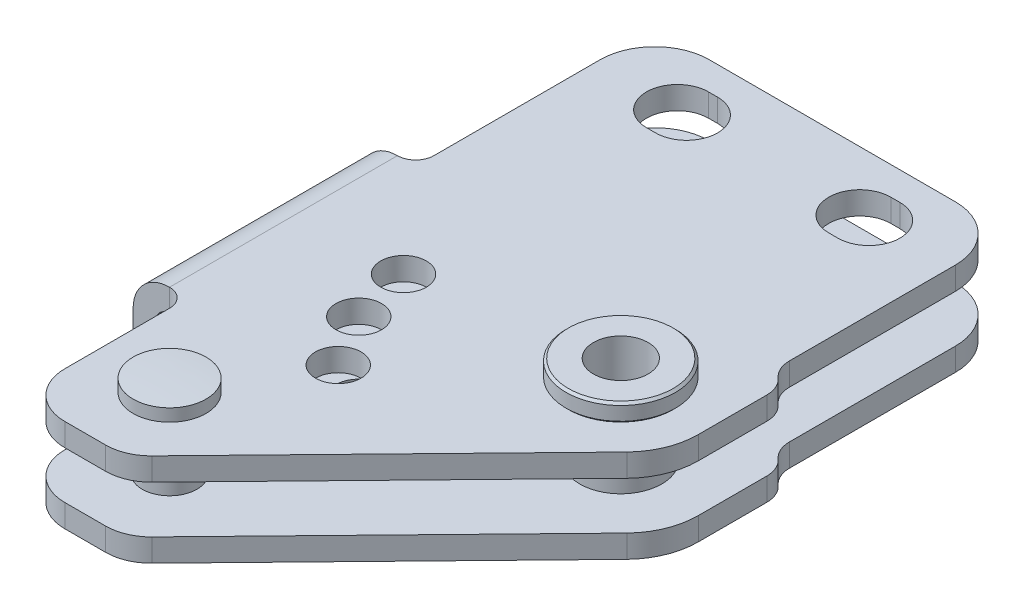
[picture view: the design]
ISO-10303-21;
HEADER;
FILE_DESCRIPTION(('STEP AP214'),'2;1');
FILE_NAME('part.step','',(''),(''),'','','');
FILE_SCHEMA(('AUTOMOTIVE_DESIGN { 1 0 10303 214 1 1 1 1 }'));
ENDSEC;
DATA;
#1=APPLICATION_CONTEXT('core data for automotive mechanical design processes');
#2=APPLICATION_PROTOCOL_DEFINITION('international standard','automotive_design',2000,#1);
#3=PRODUCT_CONTEXT('',#1,'mechanical');
#4=PRODUCT('Part','Part','',(#3));
#5=PRODUCT_RELATED_PRODUCT_CATEGORY('part','',(#4));
#6=PRODUCT_DEFINITION_FORMATION('','',#4);
#7=PRODUCT_DEFINITION_CONTEXT('part definition',#1,'design');
#8=PRODUCT_DEFINITION('design','',#6,#7);
#9=PRODUCT_DEFINITION_SHAPE('','',#8);
#10=(LENGTH_UNIT() NAMED_UNIT(*) SI_UNIT(.MILLI.,.METRE.));
#11=(NAMED_UNIT(*) PLANE_ANGLE_UNIT() SI_UNIT($,.RADIAN.));
#12=(NAMED_UNIT(*) SI_UNIT($,.STERADIAN.) SOLID_ANGLE_UNIT());
#13=UNCERTAINTY_MEASURE_WITH_UNIT(LENGTH_MEASURE(1.E-05),#10,'distance_accuracy_value','');
#14=(GEOMETRIC_REPRESENTATION_CONTEXT(3) GLOBAL_UNCERTAINTY_ASSIGNED_CONTEXT((#13)) GLOBAL_UNIT_ASSIGNED_CONTEXT((#10,
#11,#12)) REPRESENTATION_CONTEXT('',''));
#15=CARTESIAN_POINT('',(0.,0.,0.));
#16=DIRECTION('',(0.,0.,1.));
#17=DIRECTION('',(1.,0.,0.));
#18=AXIS2_PLACEMENT_3D('',#15,#16,#17);
#19=CARTESIAN_POINT('',(22.5,-5.1,28.72));
#20=DIRECTION('',(0.,-1.,0.));
#21=DIRECTION('',(-1.,0.,0.));
#22=AXIS2_PLACEMENT_3D('',#19,#20,#21);
#23=CYLINDRICAL_SURFACE('',#22,6.);
#24=CARTESIAN_POINT('',(22.5,-6.85,28.72));
#25=DIRECTION('',(0.,-1.,0.));
#26=DIRECTION('',(1.,0.,0.));
#27=AXIS2_PLACEMENT_3D('',#24,#25,#26);
#28=CIRCLE('',#27,6.);
#29=CARTESIAN_POINT('',(28.5,-6.85,28.72));
#30=VERTEX_POINT('',#29);
#31=EDGE_CURVE('E9',#30,#30,#28,.F.);
#32=ORIENTED_EDGE('',*,*,#31,.T.);
#33=EDGE_LOOP('',(#32));
#34=FACE_BOUND('',#33,.T.);
#35=CARTESIAN_POINT('',(22.5,-5.3,28.72));
#36=DIRECTION('',(0.,-1.,0.));
#37=DIRECTION('',(-1.,0.,0.));
#38=AXIS2_PLACEMENT_3D('',#35,#36,#37);
#39=CIRCLE('',#38,6.);
#40=CARTESIAN_POINT('',(16.5,-5.3,28.72));
#41=VERTEX_POINT('',#40);
#42=EDGE_CURVE('E393',#41,#41,#39,.T.);
#43=ORIENTED_EDGE('',*,*,#42,.T.);
#44=EDGE_LOOP('',(#43));
#45=FACE_BOUND('',#44,.T.);
#46=ADVANCED_FACE('F14',(#34,#45),#23,.T.);
#47=CARTESIAN_POINT('',(22.5,-7.,28.72));
#48=DIRECTION('',(0.,1.,0.));
#49=DIRECTION('',(1.,0.,0.));
#50=AXIS2_PLACEMENT_3D('',#47,#48,#49);
#51=CYLINDRICAL_SURFACE('',#50,3.);
#52=CARTESIAN_POINT('',(22.5,7.1,28.72));
#53=DIRECTION('',(0.,1.,0.));
#54=DIRECTION('',(1.,0.,0.));
#55=AXIS2_PLACEMENT_3D('',#52,#53,#54);
#56=CIRCLE('',#55,3.);
#57=CARTESIAN_POINT('',(25.5,7.1,28.72));
#58=VERTEX_POINT('',#57);
#59=EDGE_CURVE('E414',#58,#58,#56,.T.);
#60=ORIENTED_EDGE('',*,*,#59,.T.);
#61=EDGE_LOOP('',(#60));
#62=FACE_BOUND('',#61,.T.);
#63=CARTESIAN_POINT('',(22.5,-7.1,28.72));
#64=DIRECTION('',(0.,-1.,0.));
#65=DIRECTION('',(1.,0.,0.));
#66=AXIS2_PLACEMENT_3D('',#63,#64,#65);
#67=CIRCLE('',#66,3.);
#68=CARTESIAN_POINT('',(25.5,-7.1,28.72));
#69=VERTEX_POINT('',#68);
#70=EDGE_CURVE('E385',#69,#69,#67,.F.);
#71=ORIENTED_EDGE('',*,*,#70,.F.);
#72=EDGE_LOOP('',(#71));
#73=FACE_BOUND('',#72,.T.);
#74=ADVANCED_FACE('F957',(#62,#73),#51,.F.);
#75=CARTESIAN_POINT('',(22.5,-5.1,28.72));
#76=DIRECTION('',(0.,-1.,0.));
#77=DIRECTION('',(-1.,0.,0.));
#78=AXIS2_PLACEMENT_3D('',#75,#76,#77);
#79=CONICAL_SURFACE('',#78,5.8,0.785398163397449);
#80=ORIENTED_EDGE('',*,*,#42,.F.);
#81=EDGE_LOOP('',(#80));
#82=FACE_BOUND('',#81,.T.);
#83=CARTESIAN_POINT('',(22.5,-5.1,28.72));
#84=DIRECTION('',(0.,-1.,0.));
#85=DIRECTION('',(-1.,0.,0.));
#86=AXIS2_PLACEMENT_3D('',#83,#84,#85);
#87=CIRCLE('',#86,5.8);
#88=CARTESIAN_POINT('',(16.7,-5.1,28.72));
#89=VERTEX_POINT('',#88);
#90=EDGE_CURVE('E389',#89,#89,#87,.T.);
#91=ORIENTED_EDGE('',*,*,#90,.T.);
#92=EDGE_LOOP('',(#91));
#93=FACE_BOUND('',#92,.T.);
#94=ADVANCED_FACE('F924',(#82,#93),#79,.T.);
#95=CARTESIAN_POINT('',(22.5,6.85,28.72));
#96=DIRECTION('',(0.,-1.,0.));
#97=DIRECTION('',(-1.,0.,0.));
#98=AXIS2_PLACEMENT_3D('',#95,#96,#97);
#99=CONICAL_SURFACE('',#98,6.,0.785398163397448);
#100=CARTESIAN_POINT('',(22.5,7.1,28.72));
#101=DIRECTION('',(0.,1.,0.));
#102=DIRECTION('',(1.,0.,0.));
#103=AXIS2_PLACEMENT_3D('',#100,#101,#102);
#104=CIRCLE('',#103,5.75);
#105=CARTESIAN_POINT('',(28.25,7.1,28.72));
#106=VERTEX_POINT('',#105);
#107=EDGE_CURVE('E401',#106,#106,#104,.T.);
#108=ORIENTED_EDGE('',*,*,#107,.F.);
#109=EDGE_LOOP('',(#108));
#110=FACE_BOUND('',#109,.T.);
#111=CARTESIAN_POINT('',(22.5,6.85,28.72));
#112=DIRECTION('',(0.,1.,0.));
#113=DIRECTION('',(1.,0.,0.));
#114=AXIS2_PLACEMENT_3D('',#111,#112,#113);
#115=CIRCLE('',#114,6.);
#116=CARTESIAN_POINT('',(28.5,6.85,28.72));
#117=VERTEX_POINT('',#116);
#118=EDGE_CURVE('E404',#117,#117,#115,.T.);
#119=ORIENTED_EDGE('',*,*,#118,.T.);
#120=EDGE_LOOP('',(#119));
#121=FACE_BOUND('',#120,.T.);
#122=ADVANCED_FACE('F972',(#110,#121),#99,.T.);
#123=CARTESIAN_POINT('',(22.5,-7.,28.72));
#124=DIRECTION('',(0.,1.,0.));
#125=DIRECTION('',(1.,0.,0.));
#126=AXIS2_PLACEMENT_3D('',#123,#124,#125);
#127=CYLINDRICAL_SURFACE('',#126,6.);
#128=ORIENTED_EDGE('',*,*,#118,.F.);
#129=EDGE_LOOP('',(#128));
#130=FACE_BOUND('',#129,.T.);
#131=CARTESIAN_POINT('',(22.5,5.35,28.72));
#132=DIRECTION('',(0.,1.,0.));
#133=DIRECTION('',(1.,0.,0.));
#134=AXIS2_PLACEMENT_3D('',#131,#132,#133);
#135=CIRCLE('',#134,6.);
#136=CARTESIAN_POINT('',(28.5,5.35,28.72));
#137=VERTEX_POINT('',#136);
#138=EDGE_CURVE('E408',#137,#137,#135,.T.);
#139=ORIENTED_EDGE('',*,*,#138,.T.);
#140=EDGE_LOOP('',(#139));
#141=FACE_BOUND('',#140,.T.);
#142=ADVANCED_FACE('F976',(#130,#141),#127,.T.);
#143=CARTESIAN_POINT('',(-1.,-53.4000000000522,54.7199999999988));
#144=DIRECTION('',(0.,1.,0.));
#145=DIRECTION('',(0.,0.,1.));
#146=AXIS2_PLACEMENT_3D('',#143,#144,#145);
#147=SPHERICAL_SURFACE('',#146,60.0000000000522);
#148=CARTESIAN_POINT('',(-1.,6.4665181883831,54.72));
#149=DIRECTION('',(0.,1.,0.));
#150=DIRECTION('',(-1.,0.,0.));
#151=AXIS2_PLACEMENT_3D('',#148,#149,#150);
#152=CIRCLE('',#151,4.);
#153=CARTESIAN_POINT('',(-5.,6.4665181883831,54.72));
#154=VERTEX_POINT('',#153);
#155=EDGE_CURVE('E436',#154,#154,#152,.T.);
#156=ORIENTED_EDGE('',*,*,#155,.T.);
#157=EDGE_LOOP('',(#156));
#158=FACE_BOUND('',#157,.T.);
#159=ADVANCED_FACE('F955',(#158),#147,.T.);
#160=CARTESIAN_POINT('',(22.5,5.1,28.72));
#161=DIRECTION('',(0.,1.,0.));
#162=DIRECTION('',(1.,0.,0.));
#163=AXIS2_PLACEMENT_3D('',#160,#161,#162);
#164=CONICAL_SURFACE('',#163,5.75,0.785398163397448);
#165=ORIENTED_EDGE('',*,*,#138,.F.);
#166=EDGE_LOOP('',(#165));
#167=FACE_BOUND('',#166,.T.);
#168=CARTESIAN_POINT('',(22.5,5.1,28.72));
#169=DIRECTION('',(0.,1.,0.));
#170=DIRECTION('',(1.,0.,0.));
#171=AXIS2_PLACEMENT_3D('',#168,#169,#170);
#172=CIRCLE('',#171,5.75);
#173=CARTESIAN_POINT('',(28.25,5.1,28.72));
#174=VERTEX_POINT('',#173);
#175=EDGE_CURVE('E411',#174,#174,#172,.T.);
#176=ORIENTED_EDGE('',*,*,#175,.T.);
#177=EDGE_LOOP('',(#176));
#178=FACE_BOUND('',#177,.T.);
#179=ADVANCED_FACE('F981',(#167,#178),#164,.T.);
#180=CARTESIAN_POINT('',(-1.,-3.4452994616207,54.72));
#181=DIRECTION('',(0.,1.,0.));
#182=DIRECTION('',(-1.,0.,0.));
#183=AXIS2_PLACEMENT_3D('',#180,#181,#182);
#184=CYLINDRICAL_SURFACE('',#183,4.);
#185=CARTESIAN_POINT('',(-1.,5.1,54.72));
#186=DIRECTION('',(0.,1.,0.));
#187=DIRECTION('',(-1.,0.,0.));
#188=AXIS2_PLACEMENT_3D('',#185,#186,#187);
#189=CIRCLE('',#188,4.);
#190=CARTESIAN_POINT('',(-5.,5.1,54.72));
#191=VERTEX_POINT('',#190);
#192=EDGE_CURVE('E433',#191,#191,#189,.T.);
#193=ORIENTED_EDGE('',*,*,#192,.T.);
#194=EDGE_LOOP('',(#193));
#195=FACE_BOUND('',#194,.T.);
#196=ORIENTED_EDGE('',*,*,#155,.F.);
#197=EDGE_LOOP('',(#196));
#198=FACE_BOUND('',#197,.T.);
#199=ADVANCED_FACE('F984',(#195,#198),#184,.T.);
#200=CARTESIAN_POINT('',(1.,5.1,-3.4));
#201=DIRECTION('',(0.,0.,1.));
#202=DIRECTION('',(0.,1.,0.));
#203=AXIS2_PLACEMENT_3D('',#200,#201,#202);
#204=PLANE('',#203);
#205=DIRECTION('',(0.,-1.,0.));
#206=VECTOR('',#205,1.);
#207=CARTESIAN_POINT('',(1.,5.1,-3.4));
#208=LINE('',#207,#206);
#209=CARTESIAN_POINT('',(1.,5.1,-3.4));
#210=VERTEX_POINT('',#209);
#211=CARTESIAN_POINT('',(1.,2.6,-3.4));
#212=VERTEX_POINT('',#211);
#213=EDGE_CURVE('E448',#210,#212,#208,.T.);
#214=ORIENTED_EDGE('',*,*,#213,.F.);
#215=DIRECTION('',(-1.,0.,0.));
#216=VECTOR('',#215,1.);
#217=CARTESIAN_POINT('',(1.,5.1,-3.4));
#218=LINE('',#217,#216);
#219=CARTESIAN_POINT('',(0.,5.1,-3.4));
#220=VERTEX_POINT('',#219);
#221=EDGE_CURVE('E442',#210,#220,#218,.T.);
#222=ORIENTED_EDGE('',*,*,#221,.T.);
#223=DIRECTION('',(0.,-1.,0.));
#224=VECTOR('',#223,1.);
#225=CARTESIAN_POINT('',(0.,5.1,-3.4));
#226=LINE('',#225,#224);
#227=CARTESIAN_POINT('',(0.,2.6,-3.4));
#228=VERTEX_POINT('',#227);
#229=EDGE_CURVE('E360',#220,#228,#226,.T.);
#230=ORIENTED_EDGE('',*,*,#229,.T.);
#231=DIRECTION('',(-1.,0.,0.));
#232=VECTOR('',#231,1.);
#233=CARTESIAN_POINT('',(34.5,2.6,-3.4));
#234=LINE('',#233,#232);
#235=EDGE_CURVE('E376',#212,#228,#234,.T.);
#236=ORIENTED_EDGE('',*,*,#235,.F.);
#237=EDGE_LOOP('',(#214,#222,#230,#236));
#238=FACE_BOUND('',#237,.T.);
#239=ADVANCED_FACE('F1093',(#238),#204,.T.);
#240=CARTESIAN_POINT('',(1.,5.1,0.));
#241=DIRECTION('',(0.,-1.,0.));
#242=DIRECTION('',(1.,0.,0.));
#243=AXIS2_PLACEMENT_3D('',#240,#241,#242);
#244=CYLINDRICAL_SURFACE('',#243,3.4);
#245=DIRECTION('',(0.,-1.,0.));
#246=VECTOR('',#245,1.);
#247=CARTESIAN_POINT('',(1.,5.1,3.4));
#248=LINE('',#247,#246);
#249=CARTESIAN_POINT('',(1.,5.1,3.4));
#250=VERTEX_POINT('',#249);
#251=CARTESIAN_POINT('',(1.,2.6,3.4));
#252=VERTEX_POINT('',#251);
#253=EDGE_CURVE('E367',#250,#252,#248,.T.);
#254=ORIENTED_EDGE('',*,*,#253,.F.);
#255=CARTESIAN_POINT('',(1.,5.1,0.));
#256=DIRECTION('',(0.,1.,0.));
#257=DIRECTION('',(-1.,0.,0.));
#258=AXIS2_PLACEMENT_3D('',#255,#256,#257);
#259=CIRCLE('',#258,3.4);
#260=EDGE_CURVE('E440',#250,#210,#259,.T.);
#261=ORIENTED_EDGE('',*,*,#260,.T.);
#262=ORIENTED_EDGE('',*,*,#213,.T.);
#263=CARTESIAN_POINT('',(1.,2.6,0.));
#264=DIRECTION('',(0.,-1.,0.));
#265=DIRECTION('',(1.,0.,0.));
#266=AXIS2_PLACEMENT_3D('',#263,#264,#265);
#267=CIRCLE('',#266,3.4);
#268=EDGE_CURVE('E371',#252,#212,#267,.F.);
#269=ORIENTED_EDGE('',*,*,#268,.F.);
#270=EDGE_LOOP('',(#254,#261,#262,#269));
#271=FACE_BOUND('',#270,.T.);
#272=ADVANCED_FACE('F1104',(#271),#244,.F.);
#273=CARTESIAN_POINT('',(0.,5.1,3.4));
#274=DIRECTION('',(0.,0.,-1.));
#275=DIRECTION('',(0.,-1.,0.));
#276=AXIS2_PLACEMENT_3D('',#273,#274,#275);
#277=PLANE('',#276);
#278=DIRECTION('',(0.,-1.,0.));
#279=VECTOR('',#278,1.);
#280=CARTESIAN_POINT('',(0.,5.1,3.4));
#281=LINE('',#280,#279);
#282=CARTESIAN_POINT('',(0.,5.1,3.4));
#283=VERTEX_POINT('',#282);
#284=CARTESIAN_POINT('',(0.,2.6,3.4));
#285=VERTEX_POINT('',#284);
#286=EDGE_CURVE('E350',#283,#285,#281,.T.);
#287=ORIENTED_EDGE('',*,*,#286,.F.);
#288=DIRECTION('',(1.,0.,0.));
#289=VECTOR('',#288,1.);
#290=CARTESIAN_POINT('',(0.,5.1,3.4));
#291=LINE('',#290,#289);
#292=EDGE_CURVE('E387',#283,#250,#291,.T.);
#293=ORIENTED_EDGE('',*,*,#292,.T.);
#294=ORIENTED_EDGE('',*,*,#253,.T.);
#295=DIRECTION('',(1.,0.,0.));
#296=VECTOR('',#295,1.);
#297=CARTESIAN_POINT('',(34.5,2.6,3.4));
#298=LINE('',#297,#296);
#299=EDGE_CURVE('E364',#285,#252,#298,.T.);
#300=ORIENTED_EDGE('',*,*,#299,.F.);
#301=EDGE_LOOP('',(#287,#293,#294,#300));
#302=FACE_BOUND('',#301,.T.);
#303=ADVANCED_FACE('F365',(#302),#277,.T.);
#304=CARTESIAN_POINT('',(0.,5.1,0.));
#305=DIRECTION('',(0.,-1.,0.));
#306=DIRECTION('',(1.,0.,0.));
#307=AXIS2_PLACEMENT_3D('',#304,#305,#306);
#308=CYLINDRICAL_SURFACE('',#307,3.4);
#309=ORIENTED_EDGE('',*,*,#229,.F.);
#310=CARTESIAN_POINT('',(0.,5.1,0.));
#311=DIRECTION('',(0.,1.,0.));
#312=DIRECTION('',(1.,0.,0.));
#313=AXIS2_PLACEMENT_3D('',#310,#311,#312);
#314=CIRCLE('',#313,3.4);
#315=EDGE_CURVE('E357',#220,#283,#314,.T.);
#316=ORIENTED_EDGE('',*,*,#315,.T.);
#317=ORIENTED_EDGE('',*,*,#286,.T.);
#318=CARTESIAN_POINT('',(0.,2.6,0.));
#319=DIRECTION('',(0.,-1.,0.));
#320=DIRECTION('',(1.,0.,0.));
#321=AXIS2_PLACEMENT_3D('',#318,#319,#320);
#322=CIRCLE('',#321,3.4);
#323=EDGE_CURVE('E354',#228,#285,#322,.F.);
#324=ORIENTED_EDGE('',*,*,#323,.F.);
#325=EDGE_LOOP('',(#309,#316,#317,#324));
#326=FACE_BOUND('',#325,.T.);
#327=ADVANCED_FACE('F352',(#326),#308,.F.);
#328=CARTESIAN_POINT('',(5.647022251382,5.1,42.861327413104));
#329=DIRECTION('',(0.,-1.,0.));
#330=DIRECTION('',(1.,0.,0.));
#331=AXIS2_PLACEMENT_3D('',#328,#329,#330);
#332=CYLINDRICAL_SURFACE('',#331,2.5);
#333=CARTESIAN_POINT('',(5.647022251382,2.6,42.861327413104));
#334=DIRECTION('',(0.,-1.,0.));
#335=DIRECTION('',(1.,0.,0.));
#336=AXIS2_PLACEMENT_3D('',#333,#334,#335);
#337=CIRCLE('',#336,2.5);
#338=CARTESIAN_POINT('',(8.147022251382,2.6,42.861327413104));
#339=VERTEX_POINT('',#338);
#340=EDGE_CURVE('E521',#339,#339,#337,.F.);
#341=ORIENTED_EDGE('',*,*,#340,.F.);
#342=EDGE_LOOP('',(#341));
#343=FACE_BOUND('',#342,.T.);
#344=CARTESIAN_POINT('',(5.647022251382,5.1,42.861327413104));
#345=DIRECTION('',(0.,1.,0.));
#346=DIRECTION('',(-1.,0.,0.));
#347=AXIS2_PLACEMENT_3D('',#344,#345,#346);
#348=CIRCLE('',#347,2.5);
#349=CARTESIAN_POINT('',(3.147022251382,5.1,42.861327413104));
#350=VERTEX_POINT('',#349);
#351=EDGE_CURVE('E518',#350,#350,#348,.T.);
#352=ORIENTED_EDGE('',*,*,#351,.T.);
#353=EDGE_LOOP('',(#352));
#354=FACE_BOUND('',#353,.T.);
#355=ADVANCED_FACE('F1091',(#343,#354),#332,.F.);
#356=CARTESIAN_POINT('',(0.583716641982,5.1,30.637426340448));
#357=DIRECTION('',(0.,-1.,0.));
#358=DIRECTION('',(1.,0.,0.));
#359=AXIS2_PLACEMENT_3D('',#356,#357,#358);
#360=CYLINDRICAL_SURFACE('',#359,2.5);
#361=CARTESIAN_POINT('',(0.583716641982,2.6,30.637426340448));
#362=DIRECTION('',(0.,-1.,0.));
#363=DIRECTION('',(1.,0.,0.));
#364=AXIS2_PLACEMENT_3D('',#361,#362,#363);
#365=CIRCLE('',#364,2.5);
#366=CARTESIAN_POINT('',(3.083716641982,2.6,30.637426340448));
#367=VERTEX_POINT('',#366);
#368=EDGE_CURVE('E537',#367,#367,#365,.F.);
#369=ORIENTED_EDGE('',*,*,#368,.F.);
#370=EDGE_LOOP('',(#369));
#371=FACE_BOUND('',#370,.T.);
#372=CARTESIAN_POINT('',(0.583716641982,5.1,30.637426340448));
#373=DIRECTION('',(0.,1.,0.));
#374=DIRECTION('',(-1.,0.,0.));
#375=AXIS2_PLACEMENT_3D('',#372,#373,#374);
#376=CIRCLE('',#375,2.5);
#377=CARTESIAN_POINT('',(-1.916283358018,5.1,30.637426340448));
#378=VERTEX_POINT('',#377);
#379=EDGE_CURVE('E534',#378,#378,#376,.T.);
#380=ORIENTED_EDGE('',*,*,#379,.T.);
#381=EDGE_LOOP('',(#380));
#382=FACE_BOUND('',#381,.T.);
#383=ADVANCED_FACE('F1099',(#371,#382),#360,.F.);
#384=CARTESIAN_POINT('',(-2.99999999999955,-5.1,-0.49999999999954));
#385=DIRECTION('',(0.,1.,0.));
#386=DIRECTION('',(-1.,0.,0.));
#387=AXIS2_PLACEMENT_3D('',#384,#385,#386);
#388=CYLINDRICAL_SURFACE('',#387,6.00000000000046);
#389=DIRECTION('',(0.,1.,0.));
#390=VECTOR('',#389,1.);
#391=CARTESIAN_POINT('',(-3.,-5.1,-6.5));
#392=LINE('',#391,#390);
#393=CARTESIAN_POINT('',(-2.99999999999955,2.6,-6.5));
#394=VERTEX_POINT('',#393);
#395=CARTESIAN_POINT('',(-3.,5.1,-6.5));
#396=VERTEX_POINT('',#395);
#397=EDGE_CURVE('E820',#394,#396,#392,.T.);
#398=ORIENTED_EDGE('',*,*,#397,.F.);
#399=CARTESIAN_POINT('',(-2.99999999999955,2.6,-0.49999999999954));
#400=DIRECTION('',(0.,-1.,0.));
#401=DIRECTION('',(1.,0.,0.));
#402=AXIS2_PLACEMENT_3D('',#399,#400,#401);
#403=CIRCLE('',#402,6.00000000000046);
#404=CARTESIAN_POINT('',(-9.,2.6,-0.49999999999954));
#405=VERTEX_POINT('',#404);
#406=EDGE_CURVE('E624',#394,#405,#403,.F.);
#407=ORIENTED_EDGE('',*,*,#406,.T.);
#408=DIRECTION('',(0.,1.,0.));
#409=VECTOR('',#408,1.);
#410=CARTESIAN_POINT('',(-9.,-5.1,-0.49999999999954));
#411=LINE('',#410,#409);
#412=CARTESIAN_POINT('',(-9.,5.1,-0.49999999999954));
#413=VERTEX_POINT('',#412);
#414=EDGE_CURVE('E816',#405,#413,#411,.T.);
#415=ORIENTED_EDGE('',*,*,#414,.T.);
#416=CARTESIAN_POINT('',(-2.99999999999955,5.1,-0.49999999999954));
#417=DIRECTION('',(0.,1.,0.));
#418=DIRECTION('',(1.,0.,0.));
#419=AXIS2_PLACEMENT_3D('',#416,#417,#418);
#420=CIRCLE('',#419,6.00000000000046);
#421=EDGE_CURVE('E694',#396,#413,#420,.T.);
#422=ORIENTED_EDGE('',*,*,#421,.F.);
#423=EDGE_LOOP('',(#398,#407,#415,#422));
#424=FACE_BOUND('',#423,.T.);
#425=ADVANCED_FACE('F1172',(#424),#388,.T.);
#426=CARTESIAN_POINT('',(-4.00000000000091,-5.1,58.2200000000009));
#427=DIRECTION('',(0.,1.,0.));
#428=DIRECTION('',(-1.,0.,0.));
#429=AXIS2_PLACEMENT_3D('',#426,#427,#428);
#430=CYLINDRICAL_SURFACE('',#429,4.99999999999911);
#431=DIRECTION('',(0.,1.,0.));
#432=VECTOR('',#431,1.);
#433=CARTESIAN_POINT('',(-9.,-5.1,58.22));
#434=LINE('',#433,#432);
#435=CARTESIAN_POINT('',(-9.,2.6,58.22));
#436=VERTEX_POINT('',#435);
#437=CARTESIAN_POINT('',(-9.,5.1,58.22));
#438=VERTEX_POINT('',#437);
#439=EDGE_CURVE('E790',#436,#438,#434,.T.);
#440=ORIENTED_EDGE('',*,*,#439,.F.);
#441=CARTESIAN_POINT('',(-4.00000000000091,2.6,58.2200000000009));
#442=DIRECTION('',(0.,-1.,0.));
#443=DIRECTION('',(1.,0.,0.));
#444=AXIS2_PLACEMENT_3D('',#441,#442,#443);
#445=CIRCLE('',#444,4.99999999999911);
#446=CARTESIAN_POINT('',(-4.,2.6,63.22));
#447=VERTEX_POINT('',#446);
#448=EDGE_CURVE('E609',#436,#447,#445,.F.);
#449=ORIENTED_EDGE('',*,*,#448,.T.);
#450=DIRECTION('',(0.,1.,0.));
#451=VECTOR('',#450,1.);
#452=CARTESIAN_POINT('',(-4.,-5.1,63.22));
#453=LINE('',#452,#451);
#454=CARTESIAN_POINT('',(-4.,5.1,63.22));
#455=VERTEX_POINT('',#454);
#456=EDGE_CURVE('E786',#447,#455,#453,.T.);
#457=ORIENTED_EDGE('',*,*,#456,.T.);
#458=CARTESIAN_POINT('',(-4.00000000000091,5.1,58.2200000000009));
#459=DIRECTION('',(0.,1.,0.));
#460=DIRECTION('',(-1.,0.,0.));
#461=AXIS2_PLACEMENT_3D('',#458,#459,#460);
#462=CIRCLE('',#461,4.99999999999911);
#463=EDGE_CURVE('E708',#438,#455,#462,.T.);
#464=ORIENTED_EDGE('',*,*,#463,.F.);
#465=EDGE_LOOP('',(#440,#449,#457,#464));
#466=FACE_BOUND('',#465,.T.);
#467=ADVANCED_FACE('F1061',(#466),#430,.T.);
#468=CARTESIAN_POINT('',(-4.,-5.1,63.22));
#469=DIRECTION('',(0.,0.,1.));
#470=DIRECTION('',(0.,1.,0.));
#471=AXIS2_PLACEMENT_3D('',#468,#469,#470);
#472=PLANE('',#471);
#473=ORIENTED_EDGE('',*,*,#456,.F.);
#474=DIRECTION('',(-1.,0.,0.));
#475=VECTOR('',#474,1.);
#476=CARTESIAN_POINT('',(34.5,2.6,63.22));
#477=LINE('',#476,#475);
#478=CARTESIAN_POINT('',(0.480000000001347,2.6,63.22));
#479=VERTEX_POINT('',#478);
#480=EDGE_CURVE('E573',#479,#447,#477,.T.);
#481=ORIENTED_EDGE('',*,*,#480,.F.);
#482=DIRECTION('',(0.,1.,0.));
#483=VECTOR('',#482,1.);
#484=CARTESIAN_POINT('',(0.48,-5.1,63.22));
#485=LINE('',#484,#483);
#486=CARTESIAN_POINT('',(0.48,5.1,63.22));
#487=VERTEX_POINT('',#486);
#488=EDGE_CURVE('E782',#479,#487,#485,.T.);
#489=ORIENTED_EDGE('',*,*,#488,.T.);
#490=DIRECTION('',(1.,0.,0.));
#491=VECTOR('',#490,1.);
#492=CARTESIAN_POINT('',(-4.,5.1,63.22));
#493=LINE('',#492,#491);
#494=EDGE_CURVE('E710',#455,#487,#493,.T.);
#495=ORIENTED_EDGE('',*,*,#494,.F.);
#496=EDGE_LOOP('',(#473,#481,#489,#495));
#497=FACE_BOUND('',#496,.T.);
#498=ADVANCED_FACE('F1066',(#497),#472,.T.);
#499=CARTESIAN_POINT('',(0.480000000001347,-5.1,58.2200000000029));
#500=DIRECTION('',(0.,1.,0.));
#501=DIRECTION('',(-1.,0.,0.));
#502=AXIS2_PLACEMENT_3D('',#499,#500,#501);
#503=CYLINDRICAL_SURFACE('',#502,4.99999999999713);
#504=ORIENTED_EDGE('',*,*,#488,.F.);
#505=CARTESIAN_POINT('',(0.480000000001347,2.6,58.2200000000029));
#506=DIRECTION('',(0.,-1.,0.));
#507=DIRECTION('',(1.,0.,0.));
#508=AXIS2_PLACEMENT_3D('',#505,#506,#507);
#509=CIRCLE('',#508,4.99999999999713);
#510=CARTESIAN_POINT('',(4.065259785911,2.6,61.705098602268));
#511=VERTEX_POINT('',#510);
#512=EDGE_CURVE('E591',#479,#511,#509,.F.);
#513=ORIENTED_EDGE('',*,*,#512,.T.);
#514=DIRECTION('',(0.,1.,0.));
#515=VECTOR('',#514,1.);
#516=CARTESIAN_POINT('',(4.065259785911,-5.1,61.705098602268));
#517=LINE('',#516,#515);
#518=CARTESIAN_POINT('',(4.065259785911,5.1,61.705098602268));
#519=VERTEX_POINT('',#518);
#520=EDGE_CURVE('E778',#511,#519,#517,.T.);
#521=ORIENTED_EDGE('',*,*,#520,.T.);
#522=CARTESIAN_POINT('',(0.480000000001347,5.1,58.2200000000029));
#523=DIRECTION('',(0.,1.,0.));
#524=DIRECTION('',(-1.,0.,0.));
#525=AXIS2_PLACEMENT_3D('',#522,#523,#524);
#526=CIRCLE('',#525,4.99999999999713);
#527=EDGE_CURVE('E713',#487,#519,#526,.T.);
#528=ORIENTED_EDGE('',*,*,#527,.F.);
#529=EDGE_LOOP('',(#504,#513,#521,#528));
#530=FACE_BOUND('',#529,.T.);
#531=ADVANCED_FACE('F1071',(#530),#503,.T.);
#532=CARTESIAN_POINT('',(4.065259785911,-5.1,61.705098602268));
#533=DIRECTION('',(0.717051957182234,0.,0.697019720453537));
#534=DIRECTION('',(0.697019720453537,0.,-0.717051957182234));
#535=AXIS2_PLACEMENT_3D('',#532,#533,#534);
#536=PLANE('',#535);
#537=ORIENTED_EDGE('',*,*,#520,.F.);
#538=DIRECTION('',(0.697019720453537,0.,-0.717051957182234));
#539=VECTOR('',#538,1.);
#540=CARTESIAN_POINT('',(4.065259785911,2.6,61.705098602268));
#541=LINE('',#540,#539);
#542=CARTESIAN_POINT('',(29.7364156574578,2.6,35.296157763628));
#543=VERTEX_POINT('',#542);
#544=EDGE_CURVE('E588',#511,#543,#541,.T.);
#545=ORIENTED_EDGE('',*,*,#544,.T.);
#546=DIRECTION('',(0.,1.,0.));
#547=VECTOR('',#546,1.);
#548=CARTESIAN_POINT('',(29.7364156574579,-5.1,35.296157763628));
#549=LINE('',#548,#547);
#550=CARTESIAN_POINT('',(29.7364156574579,5.1,35.296157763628));
#551=VERTEX_POINT('',#550);
#552=EDGE_CURVE('E774',#543,#551,#549,.T.);
#553=ORIENTED_EDGE('',*,*,#552,.T.);
#554=DIRECTION('',(0.697019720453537,0.,-0.717051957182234));
#555=VECTOR('',#554,1.);
#556=CARTESIAN_POINT('',(4.065259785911,5.1,61.705098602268));
#557=LINE('',#556,#555);
#558=EDGE_CURVE('E716',#519,#551,#557,.T.);
#559=ORIENTED_EDGE('',*,*,#558,.F.);
#560=EDGE_LOOP('',(#537,#545,#553,#559));
#561=FACE_BOUND('',#560,.T.);
#562=ADVANCED_FACE('F1076',(#561),#536,.T.);
#563=CARTESIAN_POINT('',(24.0000000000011,-5.1,29.72));
#564=DIRECTION('',(0.,1.,0.));
#565=DIRECTION('',(-1.,0.,0.));
#566=AXIS2_PLACEMENT_3D('',#563,#564,#565);
#567=CYLINDRICAL_SURFACE('',#566,7.99999999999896);
#568=ORIENTED_EDGE('',*,*,#552,.F.);
#569=CARTESIAN_POINT('',(24.0000000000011,2.6,29.72));
#570=DIRECTION('',(0.,-1.,0.));
#571=DIRECTION('',(1.,0.,0.));
#572=AXIS2_PLACEMENT_3D('',#569,#570,#571);
#573=CIRCLE('',#572,7.99999999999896);
#574=CARTESIAN_POINT('',(32.,2.6,29.72));
#575=VERTEX_POINT('',#574);
#576=EDGE_CURVE('E844',#543,#575,#573,.F.);
#577=ORIENTED_EDGE('',*,*,#576,.T.);
#578=DIRECTION('',(0.,1.,0.));
#579=VECTOR('',#578,1.);
#580=CARTESIAN_POINT('',(32.,-5.1,29.72));
#581=LINE('',#580,#579);
#582=CARTESIAN_POINT('',(32.,5.1,29.72));
#583=VERTEX_POINT('',#582);
#584=EDGE_CURVE('E768',#575,#583,#581,.T.);
#585=ORIENTED_EDGE('',*,*,#584,.T.);
#586=CARTESIAN_POINT('',(24.0000000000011,5.1,29.72));
#587=DIRECTION('',(0.,1.,0.));
#588=DIRECTION('',(-1.,0.,0.));
#589=AXIS2_PLACEMENT_3D('',#586,#587,#588);
#590=CIRCLE('',#589,7.99999999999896);
#591=EDGE_CURVE('E719',#551,#583,#590,.T.);
#592=ORIENTED_EDGE('',*,*,#591,.F.);
#593=EDGE_LOOP('',(#568,#577,#585,#592));
#594=FACE_BOUND('',#593,.T.);
#595=ADVANCED_FACE('F944',(#594),#567,.T.);
#596=CARTESIAN_POINT('',(32.,-5.1,29.72));
#597=DIRECTION('',(1.,0.,0.));
#598=DIRECTION('',(0.,1.,0.));
#599=AXIS2_PLACEMENT_3D('',#596,#597,#598);
#600=PLANE('',#599);
#601=ORIENTED_EDGE('',*,*,#584,.F.);
#602=DIRECTION('',(0.,0.,-1.));
#603=VECTOR('',#602,1.);
#604=CARTESIAN_POINT('',(32.,2.6,29.72));
#605=LINE('',#604,#603);
#606=CARTESIAN_POINT('',(32.,2.6,22.19));
#607=VERTEX_POINT('',#606);
#608=EDGE_CURVE('E594',#575,#607,#605,.T.);
#609=ORIENTED_EDGE('',*,*,#608,.T.);
#610=DIRECTION('',(0.,1.,0.));
#611=VECTOR('',#610,1.);
#612=CARTESIAN_POINT('',(32.,-5.1,22.19));
#613=LINE('',#612,#611);
#614=CARTESIAN_POINT('',(32.,5.1,22.19));
#615=VERTEX_POINT('',#614);
#616=EDGE_CURVE('E840',#607,#615,#613,.T.);
#617=ORIENTED_EDGE('',*,*,#616,.T.);
#618=DIRECTION('',(0.,0.,-1.));
#619=VECTOR('',#618,1.);
#620=CARTESIAN_POINT('',(32.,5.1,29.72));
#621=LINE('',#620,#619);
#622=EDGE_CURVE('E678',#583,#615,#621,.T.);
#623=ORIENTED_EDGE('',*,*,#622,.F.);
#624=EDGE_LOOP('',(#601,#609,#617,#623));
#625=FACE_BOUND('',#624,.T.);
#626=ADVANCED_FACE('F1226',(#625),#600,.T.);
#627=CARTESIAN_POINT('',(29.0000000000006,-5.1,22.1899999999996));
#628=DIRECTION('',(0.,1.,0.));
#629=DIRECTION('',(-1.,0.,0.));
#630=AXIS2_PLACEMENT_3D('',#627,#628,#629);
#631=CYLINDRICAL_SURFACE('',#630,2.99999999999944);
#632=ORIENTED_EDGE('',*,*,#616,.F.);
#633=CARTESIAN_POINT('',(29.0000000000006,2.6,22.1899999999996));
#634=DIRECTION('',(0.,-1.,0.));
#635=DIRECTION('',(1.,0.,0.));
#636=AXIS2_PLACEMENT_3D('',#633,#634,#635);
#637=CIRCLE('',#636,2.99999999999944);
#638=CARTESIAN_POINT('',(31.,2.6,19.9539320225));
#639=VERTEX_POINT('',#638);
#640=EDGE_CURVE('E597',#607,#639,#637,.F.);
#641=ORIENTED_EDGE('',*,*,#640,.T.);
#642=DIRECTION('',(0.,1.,0.));
#643=VECTOR('',#642,1.);
#644=CARTESIAN_POINT('',(31.,-5.1,19.9539320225));
#645=LINE('',#644,#643);
#646=CARTESIAN_POINT('',(31.,5.1,19.9539320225));
#647=VERTEX_POINT('',#646);
#648=EDGE_CURVE('E836',#639,#647,#645,.T.);
#649=ORIENTED_EDGE('',*,*,#648,.T.);
#650=CARTESIAN_POINT('',(29.0000000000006,5.1,22.1899999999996));
#651=DIRECTION('',(0.,1.,0.));
#652=DIRECTION('',(-1.,0.,0.));
#653=AXIS2_PLACEMENT_3D('',#650,#651,#652);
#654=CIRCLE('',#653,2.99999999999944);
#655=EDGE_CURVE('E679',#615,#647,#654,.T.);
#656=ORIENTED_EDGE('',*,*,#655,.F.);
#657=EDGE_LOOP('',(#632,#641,#649,#656));
#658=FACE_BOUND('',#657,.T.);
#659=ADVANCED_FACE('F1313',(#658),#631,.T.);
#660=CARTESIAN_POINT('',(32.9999999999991,-5.1,17.7178640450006));
#661=DIRECTION('',(0.,1.,0.));
#662=DIRECTION('',(-1.,0.,0.));
#663=AXIS2_PLACEMENT_3D('',#660,#661,#662);
#664=CYLINDRICAL_SURFACE('',#663,2.99999999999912);
#665=ORIENTED_EDGE('',*,*,#648,.F.);
#666=CARTESIAN_POINT('',(32.9999999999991,2.6,17.7178640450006));
#667=DIRECTION('',(0.,-1.,0.));
#668=DIRECTION('',(1.,0.,0.));
#669=AXIS2_PLACEMENT_3D('',#666,#667,#668);
#670=CIRCLE('',#669,2.99999999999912);
#671=CARTESIAN_POINT('',(30.,2.6,17.717864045));
#672=VERTEX_POINT('',#671);
#673=EDGE_CURVE('E600',#639,#672,#670,.T.);
#674=ORIENTED_EDGE('',*,*,#673,.T.);
#675=DIRECTION('',(0.,1.,0.));
#676=VECTOR('',#675,1.);
#677=CARTESIAN_POINT('',(30.,-5.1,17.717864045));
#678=LINE('',#677,#676);
#679=CARTESIAN_POINT('',(30.,5.1,17.717864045));
#680=VERTEX_POINT('',#679);
#681=EDGE_CURVE('E832',#672,#680,#678,.T.);
#682=ORIENTED_EDGE('',*,*,#681,.T.);
#683=CARTESIAN_POINT('',(32.9999999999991,5.1,17.7178640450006));
#684=DIRECTION('',(0.,-1.,0.));
#685=DIRECTION('',(1.,0.,0.));
#686=AXIS2_PLACEMENT_3D('',#683,#684,#685);
#687=CIRCLE('',#686,2.99999999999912);
#688=EDGE_CURVE('E682',#647,#680,#687,.T.);
#689=ORIENTED_EDGE('',*,*,#688,.F.);
#690=EDGE_LOOP('',(#665,#674,#682,#689));
#691=FACE_BOUND('',#690,.T.);
#692=ADVANCED_FACE('F1234',(#691),#664,.F.);
#693=CARTESIAN_POINT('',(30.,-5.1,17.717864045));
#694=DIRECTION('',(1.,0.,0.));
#695=DIRECTION('',(0.,1.,0.));
#696=AXIS2_PLACEMENT_3D('',#693,#694,#695);
#697=PLANE('',#696);
#698=ORIENTED_EDGE('',*,*,#681,.F.);
#699=DIRECTION('',(0.,0.,-1.));
#700=VECTOR('',#699,1.);
#701=CARTESIAN_POINT('',(30.,2.6,17.717864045));
#702=LINE('',#701,#700);
#703=CARTESIAN_POINT('',(30.,2.6,-0.5));
#704=VERTEX_POINT('',#703);
#705=EDGE_CURVE('E603',#672,#704,#702,.T.);
#706=ORIENTED_EDGE('',*,*,#705,.T.);
#707=DIRECTION('',(0.,1.,0.));
#708=VECTOR('',#707,1.);
#709=CARTESIAN_POINT('',(30.,-5.1,-0.5));
#710=LINE('',#709,#708);
#711=CARTESIAN_POINT('',(30.,5.1,-0.5));
#712=VERTEX_POINT('',#711);
#713=EDGE_CURVE('E828',#704,#712,#710,.T.);
#714=ORIENTED_EDGE('',*,*,#713,.T.);
#715=DIRECTION('',(0.,0.,-1.));
#716=VECTOR('',#715,1.);
#717=CARTESIAN_POINT('',(30.,5.1,17.717864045));
#718=LINE('',#717,#716);
#719=EDGE_CURVE('E685',#680,#712,#718,.T.);
#720=ORIENTED_EDGE('',*,*,#719,.F.);
#721=EDGE_LOOP('',(#698,#706,#714,#720));
#722=FACE_BOUND('',#721,.T.);
#723=ADVANCED_FACE('F1237',(#722),#697,.T.);
#724=CARTESIAN_POINT('',(24.,-5.1,-0.5));
#725=DIRECTION('',(0.,1.,0.));
#726=DIRECTION('',(-1.,0.,0.));
#727=AXIS2_PLACEMENT_3D('',#724,#725,#726);
#728=CYLINDRICAL_SURFACE('',#727,6.);
#729=ORIENTED_EDGE('',*,*,#713,.F.);
#730=CARTESIAN_POINT('',(24.,2.6,-0.5));
#731=DIRECTION('',(0.,-1.,0.));
#732=DIRECTION('',(1.,0.,0.));
#733=AXIS2_PLACEMENT_3D('',#730,#731,#732);
#734=CIRCLE('',#733,6.);
#735=CARTESIAN_POINT('',(24.,2.6,-6.5));
#736=VERTEX_POINT('',#735);
#737=EDGE_CURVE('E606',#704,#736,#734,.F.);
#738=ORIENTED_EDGE('',*,*,#737,.T.);
#739=DIRECTION('',(0.,1.,0.));
#740=VECTOR('',#739,1.);
#741=CARTESIAN_POINT('',(24.,-5.1,-6.5));
#742=LINE('',#741,#740);
#743=CARTESIAN_POINT('',(24.,5.1,-6.5));
#744=VERTEX_POINT('',#743);
#745=EDGE_CURVE('E824',#736,#744,#742,.T.);
#746=ORIENTED_EDGE('',*,*,#745,.T.);
#747=CARTESIAN_POINT('',(24.,5.1,-0.5));
#748=DIRECTION('',(0.,1.,0.));
#749=DIRECTION('',(-1.,0.,0.));
#750=AXIS2_PLACEMENT_3D('',#747,#748,#749);
#751=CIRCLE('',#750,6.);
#752=EDGE_CURVE('E688',#712,#744,#751,.T.);
#753=ORIENTED_EDGE('',*,*,#752,.F.);
#754=EDGE_LOOP('',(#729,#738,#746,#753));
#755=FACE_BOUND('',#754,.T.);
#756=ADVANCED_FACE('F1242',(#755),#728,.T.);
#757=CARTESIAN_POINT('',(24.,-5.1,-6.5));
#758=DIRECTION('',(0.,0.,-1.));
#759=DIRECTION('',(0.,-1.,0.));
#760=AXIS2_PLACEMENT_3D('',#757,#758,#759);
#761=PLANE('',#760);
#762=ORIENTED_EDGE('',*,*,#745,.F.);
#763=DIRECTION('',(-1.,0.,0.));
#764=VECTOR('',#763,1.);
#765=CARTESIAN_POINT('',(34.5,2.6,-6.5));
#766=LINE('',#765,#764);
#767=EDGE_CURVE('E565',#736,#394,#766,.T.);
#768=ORIENTED_EDGE('',*,*,#767,.T.);
#769=ORIENTED_EDGE('',*,*,#397,.T.);
#770=DIRECTION('',(-1.,0.,0.));
#771=VECTOR('',#770,1.);
#772=CARTESIAN_POINT('',(24.,5.1,-6.5));
#773=LINE('',#772,#771);
#774=EDGE_CURVE('E691',#744,#396,#773,.T.);
#775=ORIENTED_EDGE('',*,*,#774,.F.);
#776=EDGE_LOOP('',(#762,#768,#769,#775));
#777=FACE_BOUND('',#776,.T.);
#778=ADVANCED_FACE('F1164',(#777),#761,.T.);
#779=CARTESIAN_POINT('',(2.17465028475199,5.1,37.139035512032));
#780=DIRECTION('',(0.,-1.,0.));
#781=DIRECTION('',(1.,0.,0.));
#782=AXIS2_PLACEMENT_3D('',#779,#780,#781);
#783=CYLINDRICAL_SURFACE('',#782,2.5);
#784=CARTESIAN_POINT('',(2.17465028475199,2.6,37.139035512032));
#785=DIRECTION('',(0.,-1.,0.));
#786=DIRECTION('',(1.,0.,0.));
#787=AXIS2_PLACEMENT_3D('',#784,#785,#786);
#788=CIRCLE('',#787,2.5);
#789=CARTESIAN_POINT('',(4.674650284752,2.6,37.139035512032));
#790=VERTEX_POINT('',#789);
#791=EDGE_CURVE('E529',#790,#790,#788,.F.);
#792=ORIENTED_EDGE('',*,*,#791,.F.);
#793=EDGE_LOOP('',(#792));
#794=FACE_BOUND('',#793,.T.);
#795=CARTESIAN_POINT('',(2.17465028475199,5.1,37.139035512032));
#796=DIRECTION('',(0.,1.,0.));
#797=DIRECTION('',(-1.,0.,0.));
#798=AXIS2_PLACEMENT_3D('',#795,#796,#797);
#799=CIRCLE('',#798,2.5);
#800=CARTESIAN_POINT('',(-0.325349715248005,5.1,37.139035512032));
#801=VERTEX_POINT('',#800);
#802=EDGE_CURVE('E526',#801,#801,#799,.T.);
#803=ORIENTED_EDGE('',*,*,#802,.T.);
#804=EDGE_LOOP('',(#803));
#805=FACE_BOUND('',#804,.T.);
#806=ADVANCED_FACE('F1136',(#794,#805),#783,.F.);
#807=CARTESIAN_POINT('',(21.,5.1,-3.4));
#808=DIRECTION('',(0.,0.,1.));
#809=DIRECTION('',(0.,1.,0.));
#810=AXIS2_PLACEMENT_3D('',#807,#808,#809);
#811=PLANE('',#810);
#812=DIRECTION('',(0.,-1.,0.));
#813=VECTOR('',#812,1.);
#814=CARTESIAN_POINT('',(21.,5.1,-3.4));
#815=LINE('',#814,#813);
#816=CARTESIAN_POINT('',(21.,5.1,-3.4));
#817=VERTEX_POINT('',#816);
#818=CARTESIAN_POINT('',(21.,2.6,-3.4));
#819=VERTEX_POINT('',#818);
#820=EDGE_CURVE('E489',#817,#819,#815,.T.);
#821=ORIENTED_EDGE('',*,*,#820,.F.);
#822=DIRECTION('',(-1.,0.,0.));
#823=VECTOR('',#822,1.);
#824=CARTESIAN_POINT('',(21.,5.1,-3.4));
#825=LINE('',#824,#823);
#826=CARTESIAN_POINT('',(20.,5.1,-3.4));
#827=VERTEX_POINT('',#826);
#828=EDGE_CURVE('E478',#817,#827,#825,.T.);
#829=ORIENTED_EDGE('',*,*,#828,.T.);
#830=DIRECTION('',(0.,-1.,0.));
#831=VECTOR('',#830,1.);
#832=CARTESIAN_POINT('',(20.,5.1,-3.4));
#833=LINE('',#832,#831);
#834=CARTESIAN_POINT('',(20.,2.6,-3.4));
#835=VERTEX_POINT('',#834);
#836=EDGE_CURVE('E486',#827,#835,#833,.T.);
#837=ORIENTED_EDGE('',*,*,#836,.T.);
#838=DIRECTION('',(-1.,0.,0.));
#839=VECTOR('',#838,1.);
#840=CARTESIAN_POINT('',(34.5,2.6,-3.4));
#841=LINE('',#840,#839);
#842=EDGE_CURVE('E884',#819,#835,#841,.T.);
#843=ORIENTED_EDGE('',*,*,#842,.F.);
#844=EDGE_LOOP('',(#821,#829,#837,#843));
#845=FACE_BOUND('',#844,.T.);
#846=ADVANCED_FACE('F1132',(#845),#811,.T.);
#847=CARTESIAN_POINT('',(21.,5.1,0.));
#848=DIRECTION('',(0.,-1.,0.));
#849=DIRECTION('',(1.,0.,0.));
#850=AXIS2_PLACEMENT_3D('',#847,#848,#849);
#851=CYLINDRICAL_SURFACE('',#850,3.4);
#852=DIRECTION('',(0.,-1.,0.));
#853=VECTOR('',#852,1.);
#854=CARTESIAN_POINT('',(21.,5.1,3.4));
#855=LINE('',#854,#853);
#856=CARTESIAN_POINT('',(21.,5.1,3.4));
#857=VERTEX_POINT('',#856);
#858=CARTESIAN_POINT('',(21.,2.6,3.4));
#859=VERTEX_POINT('',#858);
#860=EDGE_CURVE('E492',#857,#859,#855,.T.);
#861=ORIENTED_EDGE('',*,*,#860,.F.);
#862=CARTESIAN_POINT('',(21.,5.1,0.));
#863=DIRECTION('',(0.,1.,0.));
#864=DIRECTION('',(-1.,0.,0.));
#865=AXIS2_PLACEMENT_3D('',#862,#863,#864);
#866=CIRCLE('',#865,3.4);
#867=EDGE_CURVE('E476',#857,#817,#866,.T.);
#868=ORIENTED_EDGE('',*,*,#867,.T.);
#869=ORIENTED_EDGE('',*,*,#820,.T.);
#870=CARTESIAN_POINT('',(21.,2.6,0.));
#871=DIRECTION('',(0.,-1.,0.));
#872=DIRECTION('',(1.,0.,0.));
#873=AXIS2_PLACEMENT_3D('',#870,#871,#872);
#874=CIRCLE('',#873,3.4);
#875=EDGE_CURVE('E887',#859,#819,#874,.F.);
#876=ORIENTED_EDGE('',*,*,#875,.F.);
#877=EDGE_LOOP('',(#861,#868,#869,#876));
#878=FACE_BOUND('',#877,.T.);
#879=ADVANCED_FACE('F1135',(#878),#851,.F.);
#880=CARTESIAN_POINT('',(20.,5.1,3.4));
#881=DIRECTION('',(0.,0.,-1.));
#882=DIRECTION('',(0.,-1.,0.));
#883=AXIS2_PLACEMENT_3D('',#880,#881,#882);
#884=PLANE('',#883);
#885=DIRECTION('',(0.,-1.,0.));
#886=VECTOR('',#885,1.);
#887=CARTESIAN_POINT('',(20.,5.1,3.4));
#888=LINE('',#887,#886);
#889=CARTESIAN_POINT('',(20.,5.1,3.4));
#890=VERTEX_POINT('',#889);
#891=CARTESIAN_POINT('',(20.,2.6,3.4));
#892=VERTEX_POINT('',#891);
#893=EDGE_CURVE('E483',#890,#892,#888,.T.);
#894=ORIENTED_EDGE('',*,*,#893,.F.);
#895=DIRECTION('',(1.,0.,0.));
#896=VECTOR('',#895,1.);
#897=CARTESIAN_POINT('',(20.,5.1,3.4));
#898=LINE('',#897,#896);
#899=EDGE_CURVE('E475',#890,#857,#898,.T.);
#900=ORIENTED_EDGE('',*,*,#899,.T.);
#901=ORIENTED_EDGE('',*,*,#860,.T.);
#902=DIRECTION('',(1.,0.,0.));
#903=VECTOR('',#902,1.);
#904=CARTESIAN_POINT('',(34.5,2.6,3.4));
#905=LINE('',#904,#903);
#906=EDGE_CURVE('E890',#892,#859,#905,.T.);
#907=ORIENTED_EDGE('',*,*,#906,.F.);
#908=EDGE_LOOP('',(#894,#900,#901,#907));
#909=FACE_BOUND('',#908,.T.);
#910=ADVANCED_FACE('F1130',(#909),#884,.T.);
#911=CARTESIAN_POINT('',(20.,5.1,0.));
#912=DIRECTION('',(0.,-1.,0.));
#913=DIRECTION('',(1.,0.,0.));
#914=AXIS2_PLACEMENT_3D('',#911,#912,#913);
#915=CYLINDRICAL_SURFACE('',#914,3.4);
#916=ORIENTED_EDGE('',*,*,#836,.F.);
#917=CARTESIAN_POINT('',(20.,5.1,0.));
#918=DIRECTION('',(0.,1.,0.));
#919=DIRECTION('',(1.,0.,0.));
#920=AXIS2_PLACEMENT_3D('',#917,#918,#919);
#921=CIRCLE('',#920,3.4);
#922=EDGE_CURVE('E481',#827,#890,#921,.T.);
#923=ORIENTED_EDGE('',*,*,#922,.T.);
#924=ORIENTED_EDGE('',*,*,#893,.T.);
#925=CARTESIAN_POINT('',(20.,2.6,0.));
#926=DIRECTION('',(0.,-1.,0.));
#927=DIRECTION('',(1.,0.,0.));
#928=AXIS2_PLACEMENT_3D('',#925,#926,#927);
#929=CIRCLE('',#928,3.4);
#930=EDGE_CURVE('E881',#835,#892,#929,.F.);
#931=ORIENTED_EDGE('',*,*,#930,.F.);
#932=EDGE_LOOP('',(#916,#923,#924,#931));
#933=FACE_BOUND('',#932,.T.);
#934=ADVANCED_FACE('F997',(#933),#915,.F.);
#935=CARTESIAN_POINT('',(-1.,-4.6,54.72));
#936=DIRECTION('',(0.,-1.,0.));
#937=DIRECTION('',(1.,0.,0.));
#938=AXIS2_PLACEMENT_3D('',#935,#936,#937);
#939=CONICAL_SURFACE('',#938,2.,1.04719755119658);
#940=CARTESIAN_POINT('',(-1.,-3.4452994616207,54.72));
#941=VERTEX_POINT('',#940);
#942=VERTEX_LOOP('',#941);
#943=FACE_BOUND('',#942,.T.);
#944=CARTESIAN_POINT('',(-1.,-4.6,54.72));
#945=DIRECTION('',(0.,1.,0.));
#946=DIRECTION('',(-1.,0.,0.));
#947=AXIS2_PLACEMENT_3D('',#944,#945,#946);
#948=CIRCLE('',#947,2.);
#949=CARTESIAN_POINT('',(-3.,-4.6,54.72));
#950=VERTEX_POINT('',#949);
#951=EDGE_CURVE('E370',#950,#950,#948,.T.);
#952=ORIENTED_EDGE('',*,*,#951,.F.);
#953=EDGE_LOOP('',(#952));
#954=FACE_BOUND('',#953,.T.);
#955=ADVANCED_FACE('F993',(#943,#954),#939,.F.);
#956=CARTESIAN_POINT('',(-9.,-5.1,-0.5));
#957=DIRECTION('',(-1.,0.,0.));
#958=DIRECTION('',(0.,-1.,0.));
#959=AXIS2_PLACEMENT_3D('',#956,#957,#958);
#960=PLANE('',#959);
#961=ORIENTED_EDGE('',*,*,#414,.F.);
#962=DIRECTION('',(0.,0.,1.));
#963=VECTOR('',#962,1.);
#964=CARTESIAN_POINT('',(-9.,2.6,-0.5));
#965=LINE('',#964,#963);
#966=CARTESIAN_POINT('',(-9.,2.6,17.7199999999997));
#967=VERTEX_POINT('',#966);
#968=EDGE_CURVE('E621',#405,#967,#965,.T.);
#969=ORIENTED_EDGE('',*,*,#968,.T.);
#970=DIRECTION('',(0.,1.,0.));
#971=VECTOR('',#970,1.);
#972=CARTESIAN_POINT('',(-9.,-5.1,17.72));
#973=LINE('',#972,#971);
#974=CARTESIAN_POINT('',(-9.,5.1,17.72));
#975=VERTEX_POINT('',#974);
#976=EDGE_CURVE('E812',#967,#975,#973,.T.);
#977=ORIENTED_EDGE('',*,*,#976,.T.);
#978=DIRECTION('',(0.,0.,1.));
#979=VECTOR('',#978,1.);
#980=CARTESIAN_POINT('',(-9.,5.1,-0.5));
#981=LINE('',#980,#979);
#982=EDGE_CURVE('E696',#413,#975,#981,.T.);
#983=ORIENTED_EDGE('',*,*,#982,.F.);
#984=EDGE_LOOP('',(#961,#969,#977,#983));
#985=FACE_BOUND('',#984,.T.);
#986=ADVANCED_FACE('F996',(#985),#960,.T.);
#987=CARTESIAN_POINT('',(29.0000000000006,5.1,22.1899999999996));
#988=DIRECTION('',(0.,1.,0.));
#989=DIRECTION('',(-1.,0.,0.));
#990=AXIS2_PLACEMENT_3D('',#987,#988,#989);
#991=PLANE('',#990);
#992=ORIENTED_EDGE('',*,*,#192,.F.);
#993=EDGE_LOOP('',(#992));
#994=FACE_BOUND('',#993,.T.);
#995=ORIENTED_EDGE('',*,*,#867,.F.);
#996=ORIENTED_EDGE('',*,*,#899,.F.);
#997=ORIENTED_EDGE('',*,*,#922,.F.);
#998=ORIENTED_EDGE('',*,*,#828,.F.);
#999=EDGE_LOOP('',(#995,#996,#997,#998));
#1000=FACE_BOUND('',#999,.T.);
#1001=ORIENTED_EDGE('',*,*,#802,.F.);
#1002=EDGE_LOOP('',(#1001));
#1003=FACE_BOUND('',#1002,.T.);
#1004=DIRECTION('',(0.,0.,-1.));
#1005=VECTOR('',#1004,1.);
#1006=CARTESIAN_POINT('',(-11.,5.1,63.22));
#1007=LINE('',#1006,#1005);
#1008=CARTESIAN_POINT('',(-11.,5.1,44.72));
#1009=VERTEX_POINT('',#1008);
#1010=CARTESIAN_POINT('',(-11.,5.1,19.72));
#1011=VERTEX_POINT('',#1010);
#1012=EDGE_CURVE('E542',#1009,#1011,#1007,.T.);
#1013=ORIENTED_EDGE('',*,*,#1012,.F.);
#1014=CARTESIAN_POINT('',(-11.,5.1,46.72));
#1015=DIRECTION('',(0.,-1.,0.));
#1016=DIRECTION('',(-1.,0.,0.));
#1017=AXIS2_PLACEMENT_3D('',#1014,#1015,#1016);
#1018=CIRCLE('',#1017,2.00000000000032);
#1019=CARTESIAN_POINT('',(-9.,5.1,46.72));
#1020=VERTEX_POINT('',#1019);
#1021=EDGE_CURVE('E702',#1009,#1020,#1018,.T.);
#1022=ORIENTED_EDGE('',*,*,#1021,.T.);
#1023=DIRECTION('',(0.,0.,1.));
#1024=VECTOR('',#1023,1.);
#1025=CARTESIAN_POINT('',(-9.,5.1,46.72));
#1026=LINE('',#1025,#1024);
#1027=EDGE_CURVE('E705',#1020,#438,#1026,.T.);
#1028=ORIENTED_EDGE('',*,*,#1027,.T.);
#1029=ORIENTED_EDGE('',*,*,#463,.T.);
#1030=ORIENTED_EDGE('',*,*,#494,.T.);
#1031=ORIENTED_EDGE('',*,*,#527,.T.);
#1032=ORIENTED_EDGE('',*,*,#558,.T.);
#1033=ORIENTED_EDGE('',*,*,#591,.T.);
#1034=ORIENTED_EDGE('',*,*,#622,.T.);
#1035=ORIENTED_EDGE('',*,*,#655,.T.);
#1036=ORIENTED_EDGE('',*,*,#688,.T.);
#1037=ORIENTED_EDGE('',*,*,#719,.T.);
#1038=ORIENTED_EDGE('',*,*,#752,.T.);
#1039=ORIENTED_EDGE('',*,*,#774,.T.);
#1040=ORIENTED_EDGE('',*,*,#421,.T.);
#1041=ORIENTED_EDGE('',*,*,#982,.T.);
#1042=CARTESIAN_POINT('',(-11.,5.1,17.7199999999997));
#1043=DIRECTION('',(0.,-1.,0.));
#1044=DIRECTION('',(-1.,0.,0.));
#1045=AXIS2_PLACEMENT_3D('',#1042,#1043,#1044);
#1046=CIRCLE('',#1045,2.00000000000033);
#1047=EDGE_CURVE('E699',#975,#1011,#1046,.T.);
#1048=ORIENTED_EDGE('',*,*,#1047,.T.);
#1049=EDGE_LOOP('',(#1013,#1022,#1028,#1029,#1030,#1031,#1032,#1033,#1034,#1035,#1036,#1037,
#1038,#1039,#1040,#1041,#1048));
#1050=FACE_BOUND('',#1049,.T.);
#1051=ORIENTED_EDGE('',*,*,#379,.F.);
#1052=EDGE_LOOP('',(#1051));
#1053=FACE_BOUND('',#1052,.T.);
#1054=ORIENTED_EDGE('',*,*,#351,.F.);
#1055=EDGE_LOOP('',(#1054));
#1056=FACE_BOUND('',#1055,.T.);
#1057=ORIENTED_EDGE('',*,*,#260,.F.);
#1058=ORIENTED_EDGE('',*,*,#292,.F.);
#1059=ORIENTED_EDGE('',*,*,#315,.F.);
#1060=ORIENTED_EDGE('',*,*,#221,.F.);
#1061=EDGE_LOOP('',(#1057,#1058,#1059,#1060));
#1062=FACE_BOUND('',#1061,.T.);
#1063=ORIENTED_EDGE('',*,*,#175,.F.);
#1064=EDGE_LOOP('',(#1063));
#1065=FACE_BOUND('',#1064,.T.);
#1066=ADVANCED_FACE('F988',(#994,#1000,#1003,#1050,#1053,#1056,#1062,#1065),#991,.T.);
#1067=CARTESIAN_POINT('',(-9.,-5.1,46.72));
#1068=DIRECTION('',(-1.,0.,0.));
#1069=DIRECTION('',(0.,-1.,0.));
#1070=AXIS2_PLACEMENT_3D('',#1067,#1068,#1069);
#1071=PLANE('',#1070);
#1072=DIRECTION('',(0.,1.,0.));
#1073=VECTOR('',#1072,1.);
#1074=CARTESIAN_POINT('',(-9.,-5.1,46.72));
#1075=LINE('',#1074,#1073);
#1076=CARTESIAN_POINT('',(-9.,2.6,46.72));
#1077=VERTEX_POINT('',#1076);
#1078=EDGE_CURVE('E794',#1077,#1020,#1075,.T.);
#1079=ORIENTED_EDGE('',*,*,#1078,.F.);
#1080=DIRECTION('',(0.,0.,1.));
#1081=VECTOR('',#1080,1.);
#1082=CARTESIAN_POINT('',(-9.,2.6,46.72));
#1083=LINE('',#1082,#1081);
#1084=EDGE_CURVE('E612',#1077,#436,#1083,.T.);
#1085=ORIENTED_EDGE('',*,*,#1084,.T.);
#1086=ORIENTED_EDGE('',*,*,#439,.T.);
#1087=ORIENTED_EDGE('',*,*,#1027,.F.);
#1088=EDGE_LOOP('',(#1079,#1085,#1086,#1087));
#1089=FACE_BOUND('',#1088,.T.);
#1090=ADVANCED_FACE('F1011',(#1089),#1071,.T.);
#1091=CARTESIAN_POINT('',(34.5,2.6,63.22));
#1092=DIRECTION('',(0.,-1.,0.));
#1093=DIRECTION('',(1.,0.,0.));
#1094=AXIS2_PLACEMENT_3D('',#1091,#1092,#1093);
#1095=PLANE('',#1094);
#1096=ORIENTED_EDGE('',*,*,#930,.T.);
#1097=ORIENTED_EDGE('',*,*,#906,.T.);
#1098=ORIENTED_EDGE('',*,*,#875,.T.);
#1099=ORIENTED_EDGE('',*,*,#842,.T.);
#1100=EDGE_LOOP('',(#1096,#1097,#1098,#1099));
#1101=FACE_BOUND('',#1100,.T.);
#1102=ORIENTED_EDGE('',*,*,#791,.T.);
#1103=EDGE_LOOP('',(#1102));
#1104=FACE_BOUND('',#1103,.T.);
#1105=ORIENTED_EDGE('',*,*,#767,.F.);
#1106=ORIENTED_EDGE('',*,*,#737,.F.);
#1107=ORIENTED_EDGE('',*,*,#705,.F.);
#1108=ORIENTED_EDGE('',*,*,#673,.F.);
#1109=ORIENTED_EDGE('',*,*,#640,.F.);
#1110=ORIENTED_EDGE('',*,*,#608,.F.);
#1111=ORIENTED_EDGE('',*,*,#576,.F.);
#1112=ORIENTED_EDGE('',*,*,#544,.F.);
#1113=ORIENTED_EDGE('',*,*,#512,.F.);
#1114=ORIENTED_EDGE('',*,*,#480,.T.);
#1115=ORIENTED_EDGE('',*,*,#448,.F.);
#1116=ORIENTED_EDGE('',*,*,#1084,.F.);
#1117=CARTESIAN_POINT('',(-11.,2.6,46.72));
#1118=DIRECTION('',(0.,-1.,0.));
#1119=DIRECTION('',(1.,0.,0.));
#1120=AXIS2_PLACEMENT_3D('',#1117,#1118,#1119);
#1121=CIRCLE('',#1120,2.00000000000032);
#1122=CARTESIAN_POINT('',(-11.,2.6,44.72));
#1123=VERTEX_POINT('',#1122);
#1124=EDGE_CURVE('E615',#1123,#1077,#1121,.T.);
#1125=ORIENTED_EDGE('',*,*,#1124,.F.);
#1126=DIRECTION('',(0.,0.,-1.));
#1127=VECTOR('',#1126,1.);
#1128=CARTESIAN_POINT('',(-11.,2.6,63.22));
#1129=LINE('',#1128,#1127);
#1130=CARTESIAN_POINT('',(-11.,2.6,19.72));
#1131=VERTEX_POINT('',#1130);
#1132=EDGE_CURVE('E585',#1123,#1131,#1129,.T.);
#1133=ORIENTED_EDGE('',*,*,#1132,.T.);
#1134=CARTESIAN_POINT('',(-11.,2.6,17.7199999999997));
#1135=DIRECTION('',(0.,-1.,0.));
#1136=DIRECTION('',(1.,0.,0.));
#1137=AXIS2_PLACEMENT_3D('',#1134,#1135,#1136);
#1138=CIRCLE('',#1137,2.00000000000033);
#1139=EDGE_CURVE('E618',#967,#1131,#1138,.T.);
#1140=ORIENTED_EDGE('',*,*,#1139,.F.);
#1141=ORIENTED_EDGE('',*,*,#968,.F.);
#1142=ORIENTED_EDGE('',*,*,#406,.F.);
#1143=EDGE_LOOP('',(#1105,#1106,#1107,#1108,#1109,#1110,#1111,#1112,#1113,#1114,#1115,#1116,
#1125,#1133,#1140,#1141,#1142));
#1144=FACE_BOUND('',#1143,.T.);
#1145=CARTESIAN_POINT('',(-1.,2.6,54.72));
#1146=DIRECTION('',(0.,-1.,0.));
#1147=DIRECTION('',(1.,0.,0.));
#1148=AXIS2_PLACEMENT_3D('',#1145,#1146,#1147);
#1149=CIRCLE('',#1148,3.);
#1150=CARTESIAN_POINT('',(2.,2.6,54.72));
#1151=VERTEX_POINT('',#1150);
#1152=EDGE_CURVE('E439',#1151,#1151,#1149,.F.);
#1153=ORIENTED_EDGE('',*,*,#1152,.T.);
#1154=EDGE_LOOP('',(#1153));
#1155=FACE_BOUND('',#1154,.T.);
#1156=ORIENTED_EDGE('',*,*,#368,.T.);
#1157=EDGE_LOOP('',(#1156));
#1158=FACE_BOUND('',#1157,.T.);
#1159=ORIENTED_EDGE('',*,*,#340,.T.);
#1160=EDGE_LOOP('',(#1159));
#1161=FACE_BOUND('',#1160,.T.);
#1162=ORIENTED_EDGE('',*,*,#323,.T.);
#1163=ORIENTED_EDGE('',*,*,#299,.T.);
#1164=ORIENTED_EDGE('',*,*,#268,.T.);
#1165=ORIENTED_EDGE('',*,*,#235,.T.);
#1166=EDGE_LOOP('',(#1162,#1163,#1164,#1165));
#1167=FACE_BOUND('',#1166,.T.);
#1168=CARTESIAN_POINT('',(22.5,2.6,28.72));
#1169=DIRECTION('',(0.,-1.,0.));
#1170=DIRECTION('',(1.,0.,0.));
#1171=AXIS2_PLACEMENT_3D('',#1168,#1169,#1170);
#1172=CIRCLE('',#1171,4.5);
#1173=CARTESIAN_POINT('',(27.,2.6,28.72));
#1174=VERTEX_POINT('',#1173);
#1175=EDGE_CURVE('E417',#1174,#1174,#1172,.T.);
#1176=ORIENTED_EDGE('',*,*,#1175,.F.);
#1177=EDGE_LOOP('',(#1176));
#1178=FACE_BOUND('',#1177,.T.);
#1179=ADVANCED_FACE('F374',(#1101,#1104,#1144,#1155,#1158,#1161,#1167,#1178),#1095,.T.);
#1180=CARTESIAN_POINT('',(-1.,-3.4452994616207,54.72));
#1181=DIRECTION('',(0.,1.,0.));
#1182=DIRECTION('',(-1.,0.,0.));
#1183=AXIS2_PLACEMENT_3D('',#1180,#1181,#1182);
#1184=CYLINDRICAL_SURFACE('',#1183,2.);
#1185=ORIENTED_EDGE('',*,*,#951,.T.);
#1186=EDGE_LOOP('',(#1185));
#1187=FACE_BOUND('',#1186,.T.);
#1188=CARTESIAN_POINT('',(-1.,-6.5666574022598,54.72));
#1189=DIRECTION('',(0.,1.,0.));
#1190=DIRECTION('',(-1.,0.,0.));
#1191=AXIS2_PLACEMENT_3D('',#1188,#1189,#1190);
#1192=CIRCLE('',#1191,2.);
#1193=CARTESIAN_POINT('',(-0.999999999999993,-6.5666574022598,56.7200000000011));
#1194=VERTEX_POINT('',#1193);
#1195=EDGE_CURVE('E424',#1194,#1194,#1192,.T.);
#1196=ORIENTED_EDGE('',*,*,#1195,.F.);
#1197=EDGE_LOOP('',(#1196));
#1198=FACE_BOUND('',#1197,.T.);
#1199=ADVANCED_FACE('F951',(#1187,#1198),#1184,.F.);
#1200=CARTESIAN_POINT('',(-11.,-5.1,17.7199999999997));
#1201=DIRECTION('',(0.,1.,0.));
#1202=DIRECTION('',(-1.,0.,0.));
#1203=AXIS2_PLACEMENT_3D('',#1200,#1201,#1202);
#1204=CYLINDRICAL_SURFACE('',#1203,2.00000000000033);
#1205=ORIENTED_EDGE('',*,*,#976,.F.);
#1206=ORIENTED_EDGE('',*,*,#1139,.T.);
#1207=DIRECTION('',(0.,1.,0.));
#1208=VECTOR('',#1207,1.);
#1209=CARTESIAN_POINT('',(-11.,-5.1,19.72));
#1210=LINE('',#1209,#1208);
#1211=EDGE_CURVE('E808',#1131,#1011,#1210,.T.);
#1212=ORIENTED_EDGE('',*,*,#1211,.T.);
#1213=ORIENTED_EDGE('',*,*,#1047,.F.);
#1214=EDGE_LOOP('',(#1205,#1206,#1212,#1213));
#1215=FACE_BOUND('',#1214,.T.);
#1216=ADVANCED_FACE('F999',(#1215),#1204,.F.);
#1217=CARTESIAN_POINT('',(-11.,1.0999999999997,63.22));
#1218=DIRECTION('',(0.,0.,-1.));
#1219=DIRECTION('',(0.,-1.,0.));
#1220=AXIS2_PLACEMENT_3D('',#1217,#1218,#1219);
#1221=CYLINDRICAL_SURFACE('',#1220,4.0000000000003);
#1222=DIRECTION('',(0.,0.,-1.));
#1223=VECTOR('',#1222,1.);
#1224=CARTESIAN_POINT('',(-15.,1.1,63.22));
#1225=LINE('',#1224,#1223);
#1226=CARTESIAN_POINT('',(-15.,1.1,44.72));
#1227=VERTEX_POINT('',#1226);
#1228=CARTESIAN_POINT('',(-15.,1.1,19.72));
#1229=VERTEX_POINT('',#1228);
#1230=EDGE_CURVE('E544',#1227,#1229,#1225,.T.);
#1231=ORIENTED_EDGE('',*,*,#1230,.F.);
#1232=CARTESIAN_POINT('',(-11.,1.0999999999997,44.72));
#1233=DIRECTION('',(0.,0.,1.));
#1234=DIRECTION('',(0.,1.,0.));
#1235=AXIS2_PLACEMENT_3D('',#1232,#1233,#1234);
#1236=CIRCLE('',#1235,4.0000000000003);
#1237=EDGE_CURVE('E552',#1009,#1227,#1236,.T.);
#1238=ORIENTED_EDGE('',*,*,#1237,.F.);
#1239=ORIENTED_EDGE('',*,*,#1012,.T.);
#1240=CARTESIAN_POINT('',(-11.,1.0999999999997,19.72));
#1241=DIRECTION('',(0.,0.,-1.));
#1242=DIRECTION('',(0.,-1.,0.));
#1243=AXIS2_PLACEMENT_3D('',#1240,#1241,#1242);
#1244=CIRCLE('',#1243,4.0000000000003);
#1245=EDGE_CURVE('E555',#1229,#1011,#1244,.T.);
#1246=ORIENTED_EDGE('',*,*,#1245,.F.);
#1247=EDGE_LOOP('',(#1231,#1238,#1239,#1246));
#1248=FACE_BOUND('',#1247,.T.);
#1249=ADVANCED_FACE('F1006',(#1248),#1221,.T.);
#1250=CARTESIAN_POINT('',(-11.,-5.1,46.72));
#1251=DIRECTION('',(0.,1.,0.));
#1252=DIRECTION('',(-1.,0.,0.));
#1253=AXIS2_PLACEMENT_3D('',#1250,#1251,#1252);
#1254=CYLINDRICAL_SURFACE('',#1253,2.00000000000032);
#1255=DIRECTION('',(0.,1.,0.));
#1256=VECTOR('',#1255,1.);
#1257=CARTESIAN_POINT('',(-11.,-5.1,44.72));
#1258=LINE('',#1257,#1256);
#1259=EDGE_CURVE('E798',#1123,#1009,#1258,.T.);
#1260=ORIENTED_EDGE('',*,*,#1259,.F.);
#1261=ORIENTED_EDGE('',*,*,#1124,.T.);
#1262=ORIENTED_EDGE('',*,*,#1078,.T.);
#1263=ORIENTED_EDGE('',*,*,#1021,.F.);
#1264=EDGE_LOOP('',(#1260,#1261,#1262,#1263));
#1265=FACE_BOUND('',#1264,.T.);
#1266=ADVANCED_FACE('F1053',(#1265),#1254,.F.);
#1267=CARTESIAN_POINT('',(-11.,1.10000000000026,63.22));
#1268=DIRECTION('',(0.,0.,-1.));
#1269=DIRECTION('',(0.,-1.,0.));
#1270=AXIS2_PLACEMENT_3D('',#1267,#1268,#1269);
#1271=CYLINDRICAL_SURFACE('',#1270,1.49999999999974);
#1272=ORIENTED_EDGE('',*,*,#1132,.F.);
#1273=CARTESIAN_POINT('',(-11.,1.10000000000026,44.72));
#1274=DIRECTION('',(0.,0.,1.));
#1275=DIRECTION('',(0.,1.,0.));
#1276=AXIS2_PLACEMENT_3D('',#1273,#1274,#1275);
#1277=CIRCLE('',#1276,1.49999999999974);
#1278=CARTESIAN_POINT('',(-12.5,1.1,44.72));
#1279=VERTEX_POINT('',#1278);
#1280=EDGE_CURVE('E853',#1279,#1123,#1277,.F.);
#1281=ORIENTED_EDGE('',*,*,#1280,.F.);
#1282=DIRECTION('',(0.,0.,-1.));
#1283=VECTOR('',#1282,1.);
#1284=CARTESIAN_POINT('',(-12.5,1.1,63.22));
#1285=LINE('',#1284,#1283);
#1286=CARTESIAN_POINT('',(-12.5,1.1,19.72));
#1287=VERTEX_POINT('',#1286);
#1288=EDGE_CURVE('E582',#1279,#1287,#1285,.T.);
#1289=ORIENTED_EDGE('',*,*,#1288,.T.);
#1290=CARTESIAN_POINT('',(-11.,1.10000000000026,19.72));
#1291=DIRECTION('',(0.,0.,-1.));
#1292=DIRECTION('',(0.,-1.,0.));
#1293=AXIS2_PLACEMENT_3D('',#1290,#1291,#1292);
#1294=CIRCLE('',#1293,1.49999999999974);
#1295=EDGE_CURVE('E675',#1131,#1287,#1294,.F.);
#1296=ORIENTED_EDGE('',*,*,#1295,.F.);
#1297=EDGE_LOOP('',(#1272,#1281,#1289,#1296));
#1298=FACE_BOUND('',#1297,.T.);
#1299=ADVANCED_FACE('F943',(#1298),#1271,.F.);
#1300=CARTESIAN_POINT('',(-12.5,1.1,63.22));
#1301=DIRECTION('',(1.,0.,0.));
#1302=DIRECTION('',(0.,1.,0.));
#1303=AXIS2_PLACEMENT_3D('',#1300,#1301,#1302);
#1304=PLANE('',#1303);
#1305=ORIENTED_EDGE('',*,*,#1288,.F.);
#1306=DIRECTION('',(0.,1.,0.));
#1307=VECTOR('',#1306,1.);
#1308=CARTESIAN_POINT('',(-12.5,-5.1,44.72));
#1309=LINE('',#1308,#1307);
#1310=CARTESIAN_POINT('',(-12.5,-1.1,44.72));
#1311=VERTEX_POINT('',#1310);
#1312=EDGE_CURVE('E850',#1311,#1279,#1309,.T.);
#1313=ORIENTED_EDGE('',*,*,#1312,.F.);
#1314=DIRECTION('',(0.,0.,-1.));
#1315=VECTOR('',#1314,1.);
#1316=CARTESIAN_POINT('',(-12.5,-1.1,63.22));
#1317=LINE('',#1316,#1315);
#1318=CARTESIAN_POINT('',(-12.5,-1.1,19.72));
#1319=VERTEX_POINT('',#1318);
#1320=EDGE_CURVE('E579',#1311,#1319,#1317,.T.);
#1321=ORIENTED_EDGE('',*,*,#1320,.T.);
#1322=DIRECTION('',(0.,-1.,0.));
#1323=VECTOR('',#1322,1.);
#1324=CARTESIAN_POINT('',(-12.5,-5.1,19.72));
#1325=LINE('',#1324,#1323);
#1326=EDGE_CURVE('E672',#1287,#1319,#1325,.T.);
#1327=ORIENTED_EDGE('',*,*,#1326,.F.);
#1328=EDGE_LOOP('',(#1305,#1313,#1321,#1327));
#1329=FACE_BOUND('',#1328,.T.);
#1330=ADVANCED_FACE('F1185',(#1329),#1304,.T.);
#1331=CARTESIAN_POINT('',(-11.,-1.10000000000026,63.22));
#1332=DIRECTION('',(0.,0.,-1.));
#1333=DIRECTION('',(0.,-1.,0.));
#1334=AXIS2_PLACEMENT_3D('',#1331,#1332,#1333);
#1335=CYLINDRICAL_SURFACE('',#1334,1.49999999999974);
#1336=ORIENTED_EDGE('',*,*,#1320,.F.);
#1337=CARTESIAN_POINT('',(-11.,-1.10000000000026,44.72));
#1338=DIRECTION('',(0.,0.,1.));
#1339=DIRECTION('',(0.,1.,0.));
#1340=AXIS2_PLACEMENT_3D('',#1337,#1338,#1339);
#1341=CIRCLE('',#1340,1.49999999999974);
#1342=CARTESIAN_POINT('',(-11.,-2.6,44.72));
#1343=VERTEX_POINT('',#1342);
#1344=EDGE_CURVE('E666',#1343,#1311,#1341,.F.);
#1345=ORIENTED_EDGE('',*,*,#1344,.F.);
#1346=DIRECTION('',(0.,0.,-1.));
#1347=VECTOR('',#1346,1.);
#1348=CARTESIAN_POINT('',(-11.,-2.6,63.22));
#1349=LINE('',#1348,#1347);
#1350=CARTESIAN_POINT('',(-11.,-2.6,19.72));
#1351=VERTEX_POINT('',#1350);
#1352=EDGE_CURVE('E575',#1343,#1351,#1349,.T.);
#1353=ORIENTED_EDGE('',*,*,#1352,.T.);
#1354=CARTESIAN_POINT('',(-11.,-1.10000000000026,19.72));
#1355=DIRECTION('',(0.,0.,-1.));
#1356=DIRECTION('',(0.,-1.,0.));
#1357=AXIS2_PLACEMENT_3D('',#1354,#1355,#1356);
#1358=CIRCLE('',#1357,1.49999999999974);
#1359=EDGE_CURVE('E669',#1319,#1351,#1358,.F.);
#1360=ORIENTED_EDGE('',*,*,#1359,.F.);
#1361=EDGE_LOOP('',(#1336,#1345,#1353,#1360));
#1362=FACE_BOUND('',#1361,.T.);
#1363=ADVANCED_FACE('F953',(#1362),#1335,.F.);
#1364=CARTESIAN_POINT('',(-1.,-3.4452994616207,54.72));
#1365=DIRECTION('',(0.,1.,0.));
#1366=DIRECTION('',(-1.,0.,0.));
#1367=AXIS2_PLACEMENT_3D('',#1364,#1365,#1366);
#1368=CYLINDRICAL_SURFACE('',#1367,3.);
#1369=ORIENTED_EDGE('',*,*,#1152,.F.);
#1370=EDGE_LOOP('',(#1369));
#1371=FACE_BOUND('',#1370,.T.);
#1372=CARTESIAN_POINT('',(-1.,-2.6,54.72));
#1373=DIRECTION('',(0.,1.,0.));
#1374=DIRECTION('',(-1.,0.,0.));
#1375=AXIS2_PLACEMENT_3D('',#1372,#1373,#1374);
#1376=CIRCLE('',#1375,3.);
#1377=CARTESIAN_POINT('',(-4.,-2.6,54.72));
#1378=VERTEX_POINT('',#1377);
#1379=EDGE_CURVE('E405',#1378,#1378,#1376,.T.);
#1380=ORIENTED_EDGE('',*,*,#1379,.T.);
#1381=EDGE_LOOP('',(#1380));
#1382=FACE_BOUND('',#1381,.T.);
#1383=ADVANCED_FACE('F933',(#1371,#1382),#1368,.T.);
#1384=CARTESIAN_POINT('',(22.5,-7.,28.72));
#1385=DIRECTION('',(0.,1.,0.));
#1386=DIRECTION('',(1.,0.,0.));
#1387=AXIS2_PLACEMENT_3D('',#1384,#1385,#1386);
#1388=CYLINDRICAL_SURFACE('',#1387,4.5);
#1389=CARTESIAN_POINT('',(22.5,-2.6,28.72));
#1390=DIRECTION('',(0.,1.,0.));
#1391=DIRECTION('',(-1.,0.,0.));
#1392=AXIS2_PLACEMENT_3D('',#1389,#1390,#1391);
#1393=CIRCLE('',#1392,4.5);
#1394=CARTESIAN_POINT('',(18.,-2.6,28.72));
#1395=VERTEX_POINT('',#1394);
#1396=EDGE_CURVE('E398',#1395,#1395,#1393,.T.);
#1397=ORIENTED_EDGE('',*,*,#1396,.T.);
#1398=EDGE_LOOP('',(#1397));
#1399=FACE_BOUND('',#1398,.T.);
#1400=ORIENTED_EDGE('',*,*,#1175,.T.);
#1401=EDGE_LOOP('',(#1400));
#1402=FACE_BOUND('',#1401,.T.);
#1403=ADVANCED_FACE('F949',(#1399,#1402),#1388,.T.);
#1404=CARTESIAN_POINT('',(-1.,53.4000000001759,54.7199999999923));
#1405=DIRECTION('',(0.,1.,0.));
#1406=DIRECTION('',(0.,0.,1.));
#1407=AXIS2_PLACEMENT_3D('',#1404,#1405,#1406);
#1408=SPHERICAL_SURFACE('',#1407,60.0000000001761);
#1409=CARTESIAN_POINT('',(-1.,-6.4665181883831,54.72));
#1410=DIRECTION('',(0.,1.,0.));
#1411=DIRECTION('',(-1.,0.,0.));
#1412=AXIS2_PLACEMENT_3D('',#1409,#1410,#1411);
#1413=CIRCLE('',#1412,4.);
#1414=CARTESIAN_POINT('',(-0.999999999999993,-6.4665181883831,58.7200000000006));
#1415=VERTEX_POINT('',#1414);
#1416=EDGE_CURVE('E427',#1415,#1415,#1413,.T.);
#1417=CARTESIAN_POINT('',(-0.999999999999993,-6.5666574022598,56.7200000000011));
#1418=CARTESIAN_POINT('',(-0.999999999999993,-6.56596205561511,56.7408488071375));
#1419=CARTESIAN_POINT('',(-0.999999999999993,-6.56525583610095,56.7616972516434));
#1420=CARTESIAN_POINT('',(-0.999999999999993,-6.56382165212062,56.803393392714));
#1421=CARTESIAN_POINT('',(-0.999999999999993,-6.56309368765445,56.8242410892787));
#1422=CARTESIAN_POINT('',(-0.999999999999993,-6.56161601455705,56.8659357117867));
#1423=CARTESIAN_POINT('',(-0.999999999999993,-6.56086630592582,56.8867826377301));
#1424=CARTESIAN_POINT('',(-0.999999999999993,-6.55934514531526,56.9284756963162));
#1425=CARTESIAN_POINT('',(-0.999999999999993,-6.55857369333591,56.949321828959));
#1426=CARTESIAN_POINT('',(-0.999999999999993,-6.55700904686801,56.9910132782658));
#1427=CARTESIAN_POINT('',(-0.999999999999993,-6.55621585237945,57.0118585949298));
#1428=CARTESIAN_POINT('',(-0.999999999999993,-6.55460772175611,57.0535483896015));
#1429=CARTESIAN_POINT('',(-0.999999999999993,-6.55379278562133,57.0743928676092));
#1430=CARTESIAN_POINT('',(-0.999999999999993,-6.55214117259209,57.1160809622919));
#1431=CARTESIAN_POINT('',(-0.999999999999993,-6.55130449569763,57.1369245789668));
#1432=CARTESIAN_POINT('',(-0.999999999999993,-6.54960940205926,57.1786109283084));
#1433=CARTESIAN_POINT('',(-0.999999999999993,-6.54875098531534,57.199453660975));
#1434=CARTESIAN_POINT('',(-0.999999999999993,-6.5470124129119,57.2411382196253));
#1435=CARTESIAN_POINT('',(-0.999999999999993,-6.54613225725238,57.2619800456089));
#1436=CARTESIAN_POINT('',(-0.999999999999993,-6.54435020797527,57.3036627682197));
#1437=CARTESIAN_POINT('',(-0.999999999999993,-6.54344831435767,57.3245036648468));
#1438=CARTESIAN_POINT('',(-0.999999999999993,-6.54162279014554,57.3661845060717));
#1439=CARTESIAN_POINT('',(-0.999999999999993,-6.54069915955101,57.3870244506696));
#1440=CARTESIAN_POINT('',(-0.999999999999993,-6.53883016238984,57.4287033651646));
#1441=CARTESIAN_POINT('',(-0.999999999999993,-6.53788479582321,57.4495423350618));
#1442=CARTESIAN_POINT('',(-0.999999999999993,-6.53597232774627,57.4912192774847));
#1443=CARTESIAN_POINT('',(-0.999999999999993,-6.53500522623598,57.5120572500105));
#1444=CARTESIAN_POINT('',(-0.999999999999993,-6.53304928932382,57.5537321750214));
#1445=CARTESIAN_POINT('',(-0.999999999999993,-6.53206045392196,57.5745691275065));
#1446=CARTESIAN_POINT('',(-0.999999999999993,-6.53006105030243,57.6162419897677));
#1447=CARTESIAN_POINT('',(-0.999999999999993,-6.52905048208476,57.6370778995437));
#1448=CARTESIAN_POINT('',(-0.999999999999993,-6.52700761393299,57.6787486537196));
#1449=CARTESIAN_POINT('',(-0.999999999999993,-6.52597531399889,57.6995834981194));
#1450=CARTESIAN_POINT('',(-0.999999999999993,-6.5238889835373,57.7412520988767));
#1451=CARTESIAN_POINT('',(-0.999999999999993,-6.5228349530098,57.7620858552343));
#1452=CARTESIAN_POINT('',(-0.999999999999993,-6.52070516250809,57.8037522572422));
#1453=CARTESIAN_POINT('',(-0.999999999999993,-6.51962940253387,57.8245849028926));
#1454=CARTESIAN_POINT('',(-0.999999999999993,-6.517456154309,57.8662490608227));
#1455=CARTESIAN_POINT('',(-0.999999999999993,-6.51635866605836,57.8870805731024));
#1456=CARTESIAN_POINT('',(-0.999999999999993,-6.51414196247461,57.9287424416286));
#1457=CARTESIAN_POINT('',(-0.999999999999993,-6.51302274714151,57.9495727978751));
#1458=CARTESIAN_POINT('',(-0.999999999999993,-6.5107625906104,57.9912323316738));
#1459=CARTESIAN_POINT('',(-0.999999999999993,-6.5096216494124,58.012061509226));
#1460=CARTESIAN_POINT('',(-0.999999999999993,-6.50731804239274,58.0537186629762));
#1461=CARTESIAN_POINT('',(-0.999999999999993,-6.50615537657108,58.0745466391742));
#1462=CARTESIAN_POINT('',(-0.999999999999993,-6.50380832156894,58.1162013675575));
#1463=CARTESIAN_POINT('',(-0.999999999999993,-6.50262393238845,58.1370281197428));
#1464=CARTESIAN_POINT('',(-0.999999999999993,-6.50023343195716,58.1786803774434));
#1465=CARTESIAN_POINT('',(-0.999999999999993,-6.49902732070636,58.1995058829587));
#1466=CARTESIAN_POINT('',(-0.999999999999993,-6.49659337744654,58.2411556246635));
#1467=CARTESIAN_POINT('',(-0.999999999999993,-6.49536554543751,58.261979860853));
#1468=CARTESIAN_POINT('',(-0.999999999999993,-6.49288816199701,58.3036270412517));
#1469=CARTESIAN_POINT('',(-0.999999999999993,-6.49163861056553,58.3244499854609));
#1470=CARTESIAN_POINT('',(-0.999999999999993,-6.48911778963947,58.3660945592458));
#1471=CARTESIAN_POINT('',(-0.999999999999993,-6.48784652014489,58.3869161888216));
#1472=CARTESIAN_POINT('',(-0.999999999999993,-6.48528226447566,58.428558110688));
#1473=CARTESIAN_POINT('',(-0.999999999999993,-6.48398927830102,58.4493784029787));
#1474=CARTESIAN_POINT('',(-0.999999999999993,-6.48138159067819,58.4910176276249));
#1475=CARTESIAN_POINT('',(-0.999999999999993,-6.48006688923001,58.5118365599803));
#1476=CARTESIAN_POINT('',(-0.999999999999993,-6.47741577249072,58.5534730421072));
#1477=CARTESIAN_POINT('',(-0.999999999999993,-6.47607935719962,58.5742905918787));
#1478=CARTESIAN_POINT('',(-0.999999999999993,-6.47338481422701,58.6159242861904));
#1479=CARTESIAN_POINT('',(-0.999999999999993,-6.47202668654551,58.6367404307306));
#1480=CARTESIAN_POINT('',(-0.999999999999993,-6.4692887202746,58.6783712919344));
#1481=CARTESIAN_POINT('',(-0.999999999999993,-6.4679088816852,58.699186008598));
#1482=CARTESIAN_POINT('',(-0.999999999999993,-6.4665181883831,58.7200000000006));
#1483=B_SPLINE_CURVE_WITH_KNOTS('',3,(#1417,#1418,#1419,#1420,#1421,#1422,#1423,#1424,#1425,
#1426,#1427,#1428,#1429,#1430,#1431,#1432,#1433,#1434,#1435,#1436,#1437,#1438,#1439,#1440,#1441,
#1442,#1443,#1444,#1445,#1446,#1447,#1448,#1449,#1450,#1451,#1452,#1453,#1454,#1455,#1456,#1457,
#1458,#1459,#1460,#1461,#1462,#1463,#1464,#1465,#1466,#1467,#1468,#1469,#1470,#1471,#1472,#1473,
#1474,#1475,#1476,#1477,#1478,#1479,#1480,#1481,#1482),.UNSPECIFIED.,.F.,.F.,(4,2,2,2,2,2,2,2,2,
2,2,2,2,2,2,2,2,2,2,2,2,2,2,2,2,2,2,2,2,2,2,2,4),(0.,0.0625811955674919,0.12516239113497,
0.18774358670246,0.25032478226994,0.312905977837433,0.375487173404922,0.438068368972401,
0.500649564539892,0.563230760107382,0.625811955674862,0.688393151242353,0.750974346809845,
0.813555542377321,0.876136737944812,0.938717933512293,1.00129912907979,1.06388032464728,
1.12646152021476,1.18904271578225,1.25162391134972,1.31420510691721,1.37678630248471,
1.43936749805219,1.50194869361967,1.56452988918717,1.62711108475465,1.68969228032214,
1.75227347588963,1.81485467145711,1.87743586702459,1.94001706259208,2.00259825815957),.UNSPECIFIED.);
#1484=EDGE_CURVE('BSEAM932',#1194,#1415,#1483,.T.);
#1485=ORIENTED_EDGE('',*,*,#1195,.T.);
#1486=ORIENTED_EDGE('',*,*,#1416,.F.);
#1487=ORIENTED_EDGE('',*,*,#1484,.T.);
#1488=ORIENTED_EDGE('',*,*,#1484,.F.);
#1489=EDGE_LOOP('',(#1485,#1487,#1486,#1488));
#1490=FACE_BOUND('',#1489,.T.);
#1491=ADVANCED_FACE('F932',(#1490),#1408,.T.);
#1492=CARTESIAN_POINT('',(-11.,-5.1,19.72));
#1493=DIRECTION('',(0.,0.,-1.));
#1494=DIRECTION('',(0.,-1.,0.));
#1495=AXIS2_PLACEMENT_3D('',#1492,#1493,#1494);
#1496=PLANE('',#1495);
#1497=CARTESIAN_POINT('',(-11.,-5.1,19.72));
#1498=VERTEX_POINT('',#1497);
#1499=EDGE_CURVE('E809',#1498,#1351,#1210,.T.);
#1500=ORIENTED_EDGE('',*,*,#1499,.F.);
#1501=CARTESIAN_POINT('',(-11.,-1.0999999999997,19.72));
#1502=DIRECTION('',(0.,0.,-1.));
#1503=DIRECTION('',(0.,-1.,0.));
#1504=AXIS2_PLACEMENT_3D('',#1501,#1502,#1503);
#1505=CIRCLE('',#1504,4.0000000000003);
#1506=CARTESIAN_POINT('',(-15.,-1.0999999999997,19.72));
#1507=VERTEX_POINT('',#1506);
#1508=EDGE_CURVE('E561',#1498,#1507,#1505,.T.);
#1509=ORIENTED_EDGE('',*,*,#1508,.T.);
#1510=DIRECTION('',(0.,1.,0.));
#1511=VECTOR('',#1510,1.);
#1512=CARTESIAN_POINT('',(-15.,-5.1,19.72));
#1513=LINE('',#1512,#1511);
#1514=EDGE_CURVE('E805',#1507,#1229,#1513,.T.);
#1515=ORIENTED_EDGE('',*,*,#1514,.T.);
#1516=ORIENTED_EDGE('',*,*,#1245,.T.);
#1517=ORIENTED_EDGE('',*,*,#1211,.F.);
#1518=ORIENTED_EDGE('',*,*,#1295,.T.);
#1519=ORIENTED_EDGE('',*,*,#1326,.T.);
#1520=ORIENTED_EDGE('',*,*,#1359,.T.);
#1521=EDGE_LOOP('',(#1500,#1509,#1515,#1516,#1517,#1518,#1519,#1520));
#1522=FACE_BOUND('',#1521,.T.);
#1523=ADVANCED_FACE('F948',(#1522),#1496,.T.);
#1524=CARTESIAN_POINT('',(-15.,-5.1,19.72));
#1525=DIRECTION('',(-1.,0.,0.));
#1526=DIRECTION('',(0.,-1.,0.));
#1527=AXIS2_PLACEMENT_3D('',#1524,#1525,#1526);
#1528=PLANE('',#1527);
#1529=DIRECTION('',(0.,0.,-1.));
#1530=VECTOR('',#1529,1.);
#1531=CARTESIAN_POINT('',(-15.,-1.0999999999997,63.22));
#1532=LINE('',#1531,#1530);
#1533=CARTESIAN_POINT('',(-15.,-1.0999999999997,44.72));
#1534=VERTEX_POINT('',#1533);
#1535=EDGE_CURVE('E547',#1534,#1507,#1532,.T.);
#1536=ORIENTED_EDGE('',*,*,#1535,.F.);
#1537=DIRECTION('',(0.,1.,0.));
#1538=VECTOR('',#1537,1.);
#1539=CARTESIAN_POINT('',(-15.,-5.1,44.72));
#1540=LINE('',#1539,#1538);
#1541=EDGE_CURVE('E802',#1534,#1227,#1540,.T.);
#1542=ORIENTED_EDGE('',*,*,#1541,.T.);
#1543=ORIENTED_EDGE('',*,*,#1230,.T.);
#1544=ORIENTED_EDGE('',*,*,#1514,.F.);
#1545=EDGE_LOOP('',(#1536,#1542,#1543,#1544));
#1546=FACE_BOUND('',#1545,.T.);
#1547=ADVANCED_FACE('F1031',(#1546),#1528,.T.);
#1548=CARTESIAN_POINT('',(-15.,-5.1,44.72));
#1549=DIRECTION('',(0.,0.,1.));
#1550=DIRECTION('',(0.,1.,0.));
#1551=AXIS2_PLACEMENT_3D('',#1548,#1549,#1550);
#1552=PLANE('',#1551);
#1553=ORIENTED_EDGE('',*,*,#1541,.F.);
#1554=CARTESIAN_POINT('',(-11.,-1.0999999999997,44.72));
#1555=DIRECTION('',(0.,0.,1.));
#1556=DIRECTION('',(0.,1.,0.));
#1557=AXIS2_PLACEMENT_3D('',#1554,#1555,#1556);
#1558=CIRCLE('',#1557,4.0000000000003);
#1559=CARTESIAN_POINT('',(-11.,-5.1,44.72));
#1560=VERTEX_POINT('',#1559);
#1561=EDGE_CURVE('E558',#1534,#1560,#1558,.T.);
#1562=ORIENTED_EDGE('',*,*,#1561,.T.);
#1563=EDGE_CURVE('E799',#1560,#1343,#1258,.T.);
#1564=ORIENTED_EDGE('',*,*,#1563,.T.);
#1565=ORIENTED_EDGE('',*,*,#1344,.T.);
#1566=ORIENTED_EDGE('',*,*,#1312,.T.);
#1567=ORIENTED_EDGE('',*,*,#1280,.T.);
#1568=ORIENTED_EDGE('',*,*,#1259,.T.);
#1569=ORIENTED_EDGE('',*,*,#1237,.T.);
#1570=EDGE_LOOP('',(#1553,#1562,#1564,#1565,#1566,#1567,#1568,#1569));
#1571=FACE_BOUND('',#1570,.T.);
#1572=ADVANCED_FACE('F941',(#1571),#1552,.T.);
#1573=CARTESIAN_POINT('',(-11.,-2.6,63.22));
#1574=DIRECTION('',(0.,1.,0.));
#1575=DIRECTION('',(-1.,0.,0.));
#1576=AXIS2_PLACEMENT_3D('',#1573,#1574,#1575);
#1577=PLANE('',#1576);
#1578=DIRECTION('',(1.,0.,0.));
#1579=VECTOR('',#1578,1.);
#1580=CARTESIAN_POINT('',(-11.,-2.6,3.4));
#1581=LINE('',#1580,#1579);
#1582=CARTESIAN_POINT('',(0.,-2.6,3.4));
#1583=VERTEX_POINT('',#1582);
#1584=CARTESIAN_POINT('',(1.,-2.6,3.4));
#1585=VERTEX_POINT('',#1584);
#1586=EDGE_CURVE('E377',#1583,#1585,#1581,.T.);
#1587=ORIENTED_EDGE('',*,*,#1586,.F.);
#1588=CARTESIAN_POINT('',(0.,-2.6,0.));
#1589=DIRECTION('',(0.,1.,0.));
#1590=DIRECTION('',(-1.,0.,0.));
#1591=AXIS2_PLACEMENT_3D('',#1588,#1589,#1590);
#1592=CIRCLE('',#1591,3.4);
#1593=CARTESIAN_POINT('',(0.,-2.6,-3.4));
#1594=VERTEX_POINT('',#1593);
#1595=EDGE_CURVE('E893',#1594,#1583,#1592,.T.);
#1596=ORIENTED_EDGE('',*,*,#1595,.F.);
#1597=DIRECTION('',(-1.,0.,0.));
#1598=VECTOR('',#1597,1.);
#1599=CARTESIAN_POINT('',(-11.,-2.6,-3.4));
#1600=LINE('',#1599,#1598);
#1601=CARTESIAN_POINT('',(1.,-2.6,-3.4));
#1602=VERTEX_POINT('',#1601);
#1603=EDGE_CURVE('E895',#1602,#1594,#1600,.T.);
#1604=ORIENTED_EDGE('',*,*,#1603,.F.);
#1605=CARTESIAN_POINT('',(1.,-2.6,0.));
#1606=DIRECTION('',(0.,1.,0.));
#1607=DIRECTION('',(-1.,0.,0.));
#1608=AXIS2_PLACEMENT_3D('',#1605,#1606,#1607);
#1609=CIRCLE('',#1608,3.4);
#1610=EDGE_CURVE('E380',#1585,#1602,#1609,.T.);
#1611=ORIENTED_EDGE('',*,*,#1610,.F.);
#1612=EDGE_LOOP('',(#1587,#1596,#1604,#1611));
#1613=FACE_BOUND('',#1612,.T.);
#1614=DIRECTION('',(1.,0.,0.));
#1615=VECTOR('',#1614,1.);
#1616=CARTESIAN_POINT('',(-11.,-2.6,3.4));
#1617=LINE('',#1616,#1615);
#1618=CARTESIAN_POINT('',(20.,-2.6,3.4));
#1619=VERTEX_POINT('',#1618);
#1620=CARTESIAN_POINT('',(21.,-2.6,3.4));
#1621=VERTEX_POINT('',#1620);
#1622=EDGE_CURVE('E879',#1619,#1621,#1617,.T.);
#1623=ORIENTED_EDGE('',*,*,#1622,.F.);
#1624=CARTESIAN_POINT('',(20.,-2.6,0.));
#1625=DIRECTION('',(0.,1.,0.));
#1626=DIRECTION('',(-1.,0.,0.));
#1627=AXIS2_PLACEMENT_3D('',#1624,#1625,#1626);
#1628=CIRCLE('',#1627,3.4);
#1629=CARTESIAN_POINT('',(20.,-2.6,-3.4));
#1630=VERTEX_POINT('',#1629);
#1631=EDGE_CURVE('E856',#1630,#1619,#1628,.T.);
#1632=ORIENTED_EDGE('',*,*,#1631,.F.);
#1633=DIRECTION('',(-1.,0.,0.));
#1634=VECTOR('',#1633,1.);
#1635=CARTESIAN_POINT('',(-11.,-2.6,-3.4));
#1636=LINE('',#1635,#1634);
#1637=CARTESIAN_POINT('',(21.,-2.6,-3.4));
#1638=VERTEX_POINT('',#1637);
#1639=EDGE_CURVE('E874',#1638,#1630,#1636,.T.);
#1640=ORIENTED_EDGE('',*,*,#1639,.F.);
#1641=CARTESIAN_POINT('',(21.,-2.6,0.));
#1642=DIRECTION('',(0.,1.,0.));
#1643=DIRECTION('',(-1.,0.,0.));
#1644=AXIS2_PLACEMENT_3D('',#1641,#1642,#1643);
#1645=CIRCLE('',#1644,3.4);
#1646=EDGE_CURVE('E877',#1621,#1638,#1645,.T.);
#1647=ORIENTED_EDGE('',*,*,#1646,.F.);
#1648=EDGE_LOOP('',(#1623,#1632,#1640,#1647));
#1649=FACE_BOUND('',#1648,.T.);
#1650=CARTESIAN_POINT('',(5.647022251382,-2.6,42.861327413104));
#1651=DIRECTION('',(0.,1.,0.));
#1652=DIRECTION('',(-1.,0.,0.));
#1653=AXIS2_PLACEMENT_3D('',#1650,#1651,#1652);
#1654=CIRCLE('',#1653,2.5);
#1655=CARTESIAN_POINT('',(3.147022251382,-2.6,42.861327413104));
#1656=VERTEX_POINT('',#1655);
#1657=EDGE_CURVE('E525',#1656,#1656,#1654,.T.);
#1658=ORIENTED_EDGE('',*,*,#1657,.F.);
#1659=EDGE_LOOP('',(#1658));
#1660=FACE_BOUND('',#1659,.T.);
#1661=CARTESIAN_POINT('',(2.17465028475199,-2.6,37.139035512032));
#1662=DIRECTION('',(0.,1.,0.));
#1663=DIRECTION('',(-1.,0.,0.));
#1664=AXIS2_PLACEMENT_3D('',#1661,#1662,#1663);
#1665=CIRCLE('',#1664,2.5);
#1666=CARTESIAN_POINT('',(-0.325349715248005,-2.6,37.139035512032));
#1667=VERTEX_POINT('',#1666);
#1668=EDGE_CURVE('E533',#1667,#1667,#1665,.T.);
#1669=ORIENTED_EDGE('',*,*,#1668,.F.);
#1670=EDGE_LOOP('',(#1669));
#1671=FACE_BOUND('',#1670,.T.);
#1672=CARTESIAN_POINT('',(0.583716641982,-2.6,30.637426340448));
#1673=DIRECTION('',(0.,1.,0.));
#1674=DIRECTION('',(-1.,0.,0.));
#1675=AXIS2_PLACEMENT_3D('',#1672,#1673,#1674);
#1676=CIRCLE('',#1675,2.5);
#1677=CARTESIAN_POINT('',(-1.916283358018,-2.6,30.637426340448));
#1678=VERTEX_POINT('',#1677);
#1679=EDGE_CURVE('E541',#1678,#1678,#1676,.T.);
#1680=ORIENTED_EDGE('',*,*,#1679,.F.);
#1681=EDGE_LOOP('',(#1680));
#1682=FACE_BOUND('',#1681,.T.);
#1683=ORIENTED_EDGE('',*,*,#1379,.F.);
#1684=EDGE_LOOP('',(#1683));
#1685=FACE_BOUND('',#1684,.T.);
#1686=DIRECTION('',(0.,0.,-1.));
#1687=VECTOR('',#1686,1.);
#1688=CARTESIAN_POINT('',(-9.,-2.6,-0.5));
#1689=LINE('',#1688,#1687);
#1690=CARTESIAN_POINT('',(-9.,-2.6,17.72));
#1691=VERTEX_POINT('',#1690);
#1692=CARTESIAN_POINT('',(-9.,-2.6,-0.49999999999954));
#1693=VERTEX_POINT('',#1692);
#1694=EDGE_CURVE('E660',#1691,#1693,#1689,.T.);
#1695=ORIENTED_EDGE('',*,*,#1694,.F.);
#1696=CARTESIAN_POINT('',(-11.,-2.6,17.7199999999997));
#1697=DIRECTION('',(0.,1.,0.));
#1698=DIRECTION('',(-1.,0.,0.));
#1699=AXIS2_PLACEMENT_3D('',#1696,#1697,#1698);
#1700=CIRCLE('',#1699,2.00000000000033);
#1701=EDGE_CURVE('E657',#1351,#1691,#1700,.T.);
#1702=ORIENTED_EDGE('',*,*,#1701,.F.);
#1703=ORIENTED_EDGE('',*,*,#1352,.F.);
#1704=CARTESIAN_POINT('',(-11.,-2.6,46.72));
#1705=DIRECTION('',(0.,1.,0.));
#1706=DIRECTION('',(-1.,0.,0.));
#1707=AXIS2_PLACEMENT_3D('',#1704,#1705,#1706);
#1708=CIRCLE('',#1707,2.00000000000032);
#1709=CARTESIAN_POINT('',(-9.,-2.6,46.72));
#1710=VERTEX_POINT('',#1709);
#1711=EDGE_CURVE('E654',#1710,#1343,#1708,.T.);
#1712=ORIENTED_EDGE('',*,*,#1711,.F.);
#1713=DIRECTION('',(0.,0.,-1.));
#1714=VECTOR('',#1713,1.);
#1715=CARTESIAN_POINT('',(-9.,-2.6,46.72));
#1716=LINE('',#1715,#1714);
#1717=CARTESIAN_POINT('',(-9.,-2.6,58.2200000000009));
#1718=VERTEX_POINT('',#1717);
#1719=EDGE_CURVE('E651',#1718,#1710,#1716,.T.);
#1720=ORIENTED_EDGE('',*,*,#1719,.F.);
#1721=CARTESIAN_POINT('',(-4.00000000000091,-2.6,58.2200000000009));
#1722=DIRECTION('',(0.,1.,0.));
#1723=DIRECTION('',(-1.,0.,0.));
#1724=AXIS2_PLACEMENT_3D('',#1721,#1722,#1723);
#1725=CIRCLE('',#1724,4.99999999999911);
#1726=CARTESIAN_POINT('',(-4.,-2.6,63.22));
#1727=VERTEX_POINT('',#1726);
#1728=EDGE_CURVE('E648',#1727,#1718,#1725,.F.);
#1729=ORIENTED_EDGE('',*,*,#1728,.F.);
#1730=DIRECTION('',(1.,0.,0.));
#1731=VECTOR('',#1730,1.);
#1732=CARTESIAN_POINT('',(-11.,-2.6,63.22));
#1733=LINE('',#1732,#1731);
#1734=CARTESIAN_POINT('',(0.480000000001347,-2.6,63.22));
#1735=VERTEX_POINT('',#1734);
#1736=EDGE_CURVE('E569',#1727,#1735,#1733,.T.);
#1737=ORIENTED_EDGE('',*,*,#1736,.T.);
#1738=CARTESIAN_POINT('',(0.480000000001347,-2.6,58.2200000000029));
#1739=DIRECTION('',(0.,1.,0.));
#1740=DIRECTION('',(-1.,0.,0.));
#1741=AXIS2_PLACEMENT_3D('',#1738,#1739,#1740);
#1742=CIRCLE('',#1741,4.99999999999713);
#1743=CARTESIAN_POINT('',(4.065259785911,-2.6,61.705098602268));
#1744=VERTEX_POINT('',#1743);
#1745=EDGE_CURVE('E630',#1744,#1735,#1742,.F.);
#1746=ORIENTED_EDGE('',*,*,#1745,.F.);
#1747=DIRECTION('',(-0.697019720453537,0.,0.717051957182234));
#1748=VECTOR('',#1747,1.);
#1749=CARTESIAN_POINT('',(4.065259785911,-2.6,61.705098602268));
#1750=LINE('',#1749,#1748);
#1751=CARTESIAN_POINT('',(29.7364156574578,-2.6,35.296157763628));
#1752=VERTEX_POINT('',#1751);
#1753=EDGE_CURVE('E627',#1752,#1744,#1750,.T.);
#1754=ORIENTED_EDGE('',*,*,#1753,.F.);
#1755=CARTESIAN_POINT('',(24.0000000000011,-2.6,29.72));
#1756=DIRECTION('',(0.,1.,0.));
#1757=DIRECTION('',(-1.,0.,0.));
#1758=AXIS2_PLACEMENT_3D('',#1755,#1756,#1757);
#1759=CIRCLE('',#1758,7.99999999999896);
#1760=CARTESIAN_POINT('',(32.,-2.6,29.72));
#1761=VERTEX_POINT('',#1760);
#1762=EDGE_CURVE('E847',#1761,#1752,#1759,.F.);
#1763=ORIENTED_EDGE('',*,*,#1762,.F.);
#1764=DIRECTION('',(0.,0.,1.));
#1765=VECTOR('',#1764,1.);
#1766=CARTESIAN_POINT('',(32.,-2.6,29.72));
#1767=LINE('',#1766,#1765);
#1768=CARTESIAN_POINT('',(32.,-2.6,22.19));
#1769=VERTEX_POINT('',#1768);
#1770=EDGE_CURVE('E633',#1769,#1761,#1767,.T.);
#1771=ORIENTED_EDGE('',*,*,#1770,.F.);
#1772=CARTESIAN_POINT('',(29.0000000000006,-2.6,22.1899999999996));
#1773=DIRECTION('',(0.,1.,0.));
#1774=DIRECTION('',(-1.,0.,0.));
#1775=AXIS2_PLACEMENT_3D('',#1772,#1773,#1774);
#1776=CIRCLE('',#1775,2.99999999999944);
#1777=CARTESIAN_POINT('',(31.,-2.6,19.9539320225));
#1778=VERTEX_POINT('',#1777);
#1779=EDGE_CURVE('E636',#1778,#1769,#1776,.F.);
#1780=ORIENTED_EDGE('',*,*,#1779,.F.);
#1781=CARTESIAN_POINT('',(32.9999999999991,-2.6,17.7178640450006));
#1782=DIRECTION('',(0.,1.,0.));
#1783=DIRECTION('',(-1.,0.,0.));
#1784=AXIS2_PLACEMENT_3D('',#1781,#1782,#1783);
#1785=CIRCLE('',#1784,2.99999999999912);
#1786=CARTESIAN_POINT('',(30.,-2.6,17.7178640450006));
#1787=VERTEX_POINT('',#1786);
#1788=EDGE_CURVE('E639',#1787,#1778,#1785,.T.);
#1789=ORIENTED_EDGE('',*,*,#1788,.F.);
#1790=DIRECTION('',(0.,0.,1.));
#1791=VECTOR('',#1790,1.);
#1792=CARTESIAN_POINT('',(30.,-2.6,17.717864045));
#1793=LINE('',#1792,#1791);
#1794=CARTESIAN_POINT('',(30.,-2.6,-0.5));
#1795=VERTEX_POINT('',#1794);
#1796=EDGE_CURVE('E642',#1795,#1787,#1793,.T.);
#1797=ORIENTED_EDGE('',*,*,#1796,.F.);
#1798=CARTESIAN_POINT('',(24.,-2.6,-0.5));
#1799=DIRECTION('',(0.,1.,0.));
#1800=DIRECTION('',(-1.,0.,0.));
#1801=AXIS2_PLACEMENT_3D('',#1798,#1799,#1800);
#1802=CIRCLE('',#1801,6.);
#1803=CARTESIAN_POINT('',(24.,-2.6,-6.5));
#1804=VERTEX_POINT('',#1803);
#1805=EDGE_CURVE('E645',#1804,#1795,#1802,.F.);
#1806=ORIENTED_EDGE('',*,*,#1805,.F.);
#1807=DIRECTION('',(1.,0.,0.));
#1808=VECTOR('',#1807,1.);
#1809=CARTESIAN_POINT('',(-11.,-2.6,-6.5));
#1810=LINE('',#1809,#1808);
#1811=CARTESIAN_POINT('',(-2.99999999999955,-2.6,-6.5));
#1812=VERTEX_POINT('',#1811);
#1813=EDGE_CURVE('E564',#1812,#1804,#1810,.T.);
#1814=ORIENTED_EDGE('',*,*,#1813,.F.);
#1815=CARTESIAN_POINT('',(-2.99999999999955,-2.6,-0.49999999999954));
#1816=DIRECTION('',(0.,1.,0.));
#1817=DIRECTION('',(-1.,0.,0.));
#1818=AXIS2_PLACEMENT_3D('',#1815,#1816,#1817);
#1819=CIRCLE('',#1818,6.00000000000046);
#1820=EDGE_CURVE('E663',#1693,#1812,#1819,.F.);
#1821=ORIENTED_EDGE('',*,*,#1820,.F.);
#1822=EDGE_LOOP('',(#1695,#1702,#1703,#1712,#1720,#1729,#1737,#1746,#1754,#1763,#1771,#1780,
#1789,#1797,#1806,#1814,#1821));
#1823=FACE_BOUND('',#1822,.T.);
#1824=ORIENTED_EDGE('',*,*,#1396,.F.);
#1825=EDGE_LOOP('',(#1824));
#1826=FACE_BOUND('',#1825,.T.);
#1827=ADVANCED_FACE('F908',(#1613,#1649,#1660,#1671,#1682,#1685,#1823,#1826),#1577,.T.);
#1828=CARTESIAN_POINT('',(-1.,-3.4452994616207,54.72));
#1829=DIRECTION('',(0.,1.,0.));
#1830=DIRECTION('',(-1.,0.,0.));
#1831=AXIS2_PLACEMENT_3D('',#1828,#1829,#1830);
#1832=CYLINDRICAL_SURFACE('',#1831,4.);
#1833=ORIENTED_EDGE('',*,*,#1416,.T.);
#1834=EDGE_LOOP('',(#1833));
#1835=FACE_BOUND('',#1834,.T.);
#1836=CARTESIAN_POINT('',(-1.,-5.1,54.72));
#1837=DIRECTION('',(0.,1.,0.));
#1838=DIRECTION('',(-1.,0.,0.));
#1839=AXIS2_PLACEMENT_3D('',#1836,#1837,#1838);
#1840=CIRCLE('',#1839,4.);
#1841=CARTESIAN_POINT('',(-5.,-5.1,54.72));
#1842=VERTEX_POINT('',#1841);
#1843=EDGE_CURVE('E430',#1842,#1842,#1840,.T.);
#1844=ORIENTED_EDGE('',*,*,#1843,.F.);
#1845=EDGE_LOOP('',(#1844));
#1846=FACE_BOUND('',#1845,.T.);
#1847=ADVANCED_FACE('F928',(#1835,#1846),#1832,.T.);
#1848=CARTESIAN_POINT('',(1.,-5.1,-3.4));
#1849=DIRECTION('',(0.,0.,-1.));
#1850=DIRECTION('',(0.,-1.,0.));
#1851=AXIS2_PLACEMENT_3D('',#1848,#1849,#1850);
#1852=PLANE('',#1851);
#1853=ORIENTED_EDGE('',*,*,#1603,.T.);
#1854=DIRECTION('',(0.,1.,0.));
#1855=VECTOR('',#1854,1.);
#1856=CARTESIAN_POINT('',(0.,-5.1,-3.4));
#1857=LINE('',#1856,#1855);
#1858=CARTESIAN_POINT('',(0.,-5.1,-3.4));
#1859=VERTEX_POINT('',#1858);
#1860=EDGE_CURVE('E467',#1859,#1594,#1857,.T.);
#1861=ORIENTED_EDGE('',*,*,#1860,.F.);
#1862=DIRECTION('',(-1.,0.,0.));
#1863=VECTOR('',#1862,1.);
#1864=CARTESIAN_POINT('',(1.,-5.1,-3.4));
#1865=LINE('',#1864,#1863);
#1866=CARTESIAN_POINT('',(1.,-5.1,-3.4));
#1867=VERTEX_POINT('',#1866);
#1868=EDGE_CURVE('E456',#1867,#1859,#1865,.T.);
#1869=ORIENTED_EDGE('',*,*,#1868,.F.);
#1870=DIRECTION('',(0.,1.,0.));
#1871=VECTOR('',#1870,1.);
#1872=CARTESIAN_POINT('',(1.,-5.1,-3.4));
#1873=LINE('',#1872,#1871);
#1874=EDGE_CURVE('E469',#1867,#1602,#1873,.T.);
#1875=ORIENTED_EDGE('',*,*,#1874,.T.);
#1876=EDGE_LOOP('',(#1853,#1861,#1869,#1875));
#1877=FACE_BOUND('',#1876,.T.);
#1878=ADVANCED_FACE('F906',(#1877),#1852,.F.);
#1879=CARTESIAN_POINT('',(1.,-5.1,0.));
#1880=DIRECTION('',(0.,1.,0.));
#1881=DIRECTION('',(-1.,0.,0.));
#1882=AXIS2_PLACEMENT_3D('',#1879,#1880,#1881);
#1883=CYLINDRICAL_SURFACE('',#1882,3.4);
#1884=ORIENTED_EDGE('',*,*,#1610,.T.);
#1885=ORIENTED_EDGE('',*,*,#1874,.F.);
#1886=CARTESIAN_POINT('',(1.,-5.1,0.));
#1887=DIRECTION('',(0.,1.,0.));
#1888=DIRECTION('',(-1.,0.,0.));
#1889=AXIS2_PLACEMENT_3D('',#1886,#1887,#1888);
#1890=CIRCLE('',#1889,3.4);
#1891=CARTESIAN_POINT('',(1.,-5.1,3.4));
#1892=VERTEX_POINT('',#1891);
#1893=EDGE_CURVE('E453',#1892,#1867,#1890,.T.);
#1894=ORIENTED_EDGE('',*,*,#1893,.F.);
#1895=DIRECTION('',(0.,1.,0.));
#1896=VECTOR('',#1895,1.);
#1897=CARTESIAN_POINT('',(1.,-5.1,3.4));
#1898=LINE('',#1897,#1896);
#1899=EDGE_CURVE('E472',#1892,#1585,#1898,.T.);
#1900=ORIENTED_EDGE('',*,*,#1899,.T.);
#1901=EDGE_LOOP('',(#1884,#1885,#1894,#1900));
#1902=FACE_BOUND('',#1901,.T.);
#1903=ADVANCED_FACE('F899',(#1902),#1883,.F.);
#1904=CARTESIAN_POINT('',(0.,-5.1,3.4));
#1905=DIRECTION('',(0.,0.,1.));
#1906=DIRECTION('',(0.,1.,0.));
#1907=AXIS2_PLACEMENT_3D('',#1904,#1905,#1906);
#1908=PLANE('',#1907);
#1909=ORIENTED_EDGE('',*,*,#1586,.T.);
#1910=ORIENTED_EDGE('',*,*,#1899,.F.);
#1911=DIRECTION('',(1.,0.,0.));
#1912=VECTOR('',#1911,1.);
#1913=CARTESIAN_POINT('',(0.,-5.1,3.4));
#1914=LINE('',#1913,#1912);
#1915=CARTESIAN_POINT('',(0.,-5.1,3.4));
#1916=VERTEX_POINT('',#1915);
#1917=EDGE_CURVE('E452',#1916,#1892,#1914,.T.);
#1918=ORIENTED_EDGE('',*,*,#1917,.F.);
#1919=DIRECTION('',(0.,1.,0.));
#1920=VECTOR('',#1919,1.);
#1921=CARTESIAN_POINT('',(0.,-5.1,3.4));
#1922=LINE('',#1921,#1920);
#1923=EDGE_CURVE('E462',#1916,#1583,#1922,.T.);
#1924=ORIENTED_EDGE('',*,*,#1923,.T.);
#1925=EDGE_LOOP('',(#1909,#1910,#1918,#1924));
#1926=FACE_BOUND('',#1925,.T.);
#1927=ADVANCED_FACE('F915',(#1926),#1908,.F.);
#1928=CARTESIAN_POINT('',(0.,-5.1,0.));
#1929=DIRECTION('',(0.,1.,0.));
#1930=DIRECTION('',(-1.,0.,0.));
#1931=AXIS2_PLACEMENT_3D('',#1928,#1929,#1930);
#1932=CYLINDRICAL_SURFACE('',#1931,3.4);
#1933=ORIENTED_EDGE('',*,*,#1595,.T.);
#1934=ORIENTED_EDGE('',*,*,#1923,.F.);
#1935=CARTESIAN_POINT('',(0.,-5.1,0.));
#1936=DIRECTION('',(0.,1.,0.));
#1937=DIRECTION('',(1.,0.,0.));
#1938=AXIS2_PLACEMENT_3D('',#1935,#1936,#1937);
#1939=CIRCLE('',#1938,3.4);
#1940=EDGE_CURVE('E459',#1859,#1916,#1939,.T.);
#1941=ORIENTED_EDGE('',*,*,#1940,.F.);
#1942=ORIENTED_EDGE('',*,*,#1860,.T.);
#1943=EDGE_LOOP('',(#1933,#1934,#1941,#1942));
#1944=FACE_BOUND('',#1943,.T.);
#1945=ADVANCED_FACE('F912',(#1944),#1932,.F.);
#1946=CARTESIAN_POINT('',(21.,-5.1,-3.4));
#1947=DIRECTION('',(0.,0.,-1.));
#1948=DIRECTION('',(0.,-1.,0.));
#1949=AXIS2_PLACEMENT_3D('',#1946,#1947,#1948);
#1950=PLANE('',#1949);
#1951=ORIENTED_EDGE('',*,*,#1639,.T.);
#1952=DIRECTION('',(0.,1.,0.));
#1953=VECTOR('',#1952,1.);
#1954=CARTESIAN_POINT('',(20.,-5.1,-3.4));
#1955=LINE('',#1954,#1953);
#1956=CARTESIAN_POINT('',(20.,-5.1,-3.4));
#1957=VERTEX_POINT('',#1956);
#1958=EDGE_CURVE('E510',#1957,#1630,#1955,.T.);
#1959=ORIENTED_EDGE('',*,*,#1958,.F.);
#1960=DIRECTION('',(-1.,0.,0.));
#1961=VECTOR('',#1960,1.);
#1962=CARTESIAN_POINT('',(21.,-5.1,-3.4));
#1963=LINE('',#1962,#1961);
#1964=CARTESIAN_POINT('',(21.,-5.1,-3.4));
#1965=VERTEX_POINT('',#1964);
#1966=EDGE_CURVE('E499',#1965,#1957,#1963,.T.);
#1967=ORIENTED_EDGE('',*,*,#1966,.F.);
#1968=DIRECTION('',(0.,1.,0.));
#1969=VECTOR('',#1968,1.);
#1970=CARTESIAN_POINT('',(21.,-5.1,-3.4));
#1971=LINE('',#1970,#1969);
#1972=EDGE_CURVE('E512',#1965,#1638,#1971,.T.);
#1973=ORIENTED_EDGE('',*,*,#1972,.T.);
#1974=EDGE_LOOP('',(#1951,#1959,#1967,#1973));
#1975=FACE_BOUND('',#1974,.T.);
#1976=ADVANCED_FACE('F1122',(#1975),#1950,.F.);
#1977=CARTESIAN_POINT('',(21.,-5.1,0.));
#1978=DIRECTION('',(0.,1.,0.));
#1979=DIRECTION('',(-1.,0.,0.));
#1980=AXIS2_PLACEMENT_3D('',#1977,#1978,#1979);
#1981=CYLINDRICAL_SURFACE('',#1980,3.4);
#1982=ORIENTED_EDGE('',*,*,#1646,.T.);
#1983=ORIENTED_EDGE('',*,*,#1972,.F.);
#1984=CARTESIAN_POINT('',(21.,-5.1,0.));
#1985=DIRECTION('',(0.,1.,0.));
#1986=DIRECTION('',(-1.,0.,0.));
#1987=AXIS2_PLACEMENT_3D('',#1984,#1985,#1986);
#1988=CIRCLE('',#1987,3.4);
#1989=CARTESIAN_POINT('',(21.,-5.1,3.4));
#1990=VERTEX_POINT('',#1989);
#1991=EDGE_CURVE('E496',#1990,#1965,#1988,.T.);
#1992=ORIENTED_EDGE('',*,*,#1991,.F.);
#1993=DIRECTION('',(0.,1.,0.));
#1994=VECTOR('',#1993,1.);
#1995=CARTESIAN_POINT('',(21.,-5.1,3.4));
#1996=LINE('',#1995,#1994);
#1997=EDGE_CURVE('E515',#1990,#1621,#1996,.T.);
#1998=ORIENTED_EDGE('',*,*,#1997,.T.);
#1999=EDGE_LOOP('',(#1982,#1983,#1992,#1998));
#2000=FACE_BOUND('',#1999,.T.);
#2001=ADVANCED_FACE('F1150',(#2000),#1981,.F.);
#2002=CARTESIAN_POINT('',(20.,-5.1,3.4));
#2003=DIRECTION('',(0.,0.,1.));
#2004=DIRECTION('',(0.,1.,0.));
#2005=AXIS2_PLACEMENT_3D('',#2002,#2003,#2004);
#2006=PLANE('',#2005);
#2007=ORIENTED_EDGE('',*,*,#1622,.T.);
#2008=ORIENTED_EDGE('',*,*,#1997,.F.);
#2009=DIRECTION('',(1.,0.,0.));
#2010=VECTOR('',#2009,1.);
#2011=CARTESIAN_POINT('',(20.,-5.1,3.4));
#2012=LINE('',#2011,#2010);
#2013=CARTESIAN_POINT('',(20.,-5.1,3.4));
#2014=VERTEX_POINT('',#2013);
#2015=EDGE_CURVE('E495',#2014,#1990,#2012,.T.);
#2016=ORIENTED_EDGE('',*,*,#2015,.F.);
#2017=DIRECTION('',(0.,1.,0.));
#2018=VECTOR('',#2017,1.);
#2019=CARTESIAN_POINT('',(20.,-5.1,3.4));
#2020=LINE('',#2019,#2018);
#2021=EDGE_CURVE('E505',#2014,#1619,#2020,.T.);
#2022=ORIENTED_EDGE('',*,*,#2021,.T.);
#2023=EDGE_LOOP('',(#2007,#2008,#2016,#2022));
#2024=FACE_BOUND('',#2023,.T.);
#2025=ADVANCED_FACE('F1102',(#2024),#2006,.F.);
#2026=CARTESIAN_POINT('',(20.,-5.1,0.));
#2027=DIRECTION('',(0.,1.,0.));
#2028=DIRECTION('',(-1.,0.,0.));
#2029=AXIS2_PLACEMENT_3D('',#2026,#2027,#2028);
#2030=CYLINDRICAL_SURFACE('',#2029,3.4);
#2031=ORIENTED_EDGE('',*,*,#1631,.T.);
#2032=ORIENTED_EDGE('',*,*,#2021,.F.);
#2033=CARTESIAN_POINT('',(20.,-5.1,0.));
#2034=DIRECTION('',(0.,1.,0.));
#2035=DIRECTION('',(1.,0.,0.));
#2036=AXIS2_PLACEMENT_3D('',#2033,#2034,#2035);
#2037=CIRCLE('',#2036,3.4);
#2038=EDGE_CURVE('E502',#1957,#2014,#2037,.T.);
#2039=ORIENTED_EDGE('',*,*,#2038,.F.);
#2040=ORIENTED_EDGE('',*,*,#1958,.T.);
#2041=EDGE_LOOP('',(#2031,#2032,#2039,#2040));
#2042=FACE_BOUND('',#2041,.T.);
#2043=ADVANCED_FACE('F1144',(#2042),#2030,.F.);
#2044=CARTESIAN_POINT('',(5.647022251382,-5.1,42.861327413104));
#2045=DIRECTION('',(0.,1.,0.));
#2046=DIRECTION('',(-1.,0.,0.));
#2047=AXIS2_PLACEMENT_3D('',#2044,#2045,#2046);
#2048=CYLINDRICAL_SURFACE('',#2047,2.5);
#2049=ORIENTED_EDGE('',*,*,#1657,.T.);
#2050=EDGE_LOOP('',(#2049));
#2051=FACE_BOUND('',#2050,.T.);
#2052=CARTESIAN_POINT('',(5.647022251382,-5.1,42.861327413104));
#2053=DIRECTION('',(0.,1.,0.));
#2054=DIRECTION('',(-1.,0.,0.));
#2055=AXIS2_PLACEMENT_3D('',#2052,#2053,#2054);
#2056=CIRCLE('',#2055,2.5);
#2057=CARTESIAN_POINT('',(3.147022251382,-5.1,42.861327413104));
#2058=VERTEX_POINT('',#2057);
#2059=EDGE_CURVE('E522',#2058,#2058,#2056,.T.);
#2060=ORIENTED_EDGE('',*,*,#2059,.F.);
#2061=EDGE_LOOP('',(#2060));
#2062=FACE_BOUND('',#2061,.T.);
#2063=ADVANCED_FACE('F1103',(#2051,#2062),#2048,.F.);
#2064=CARTESIAN_POINT('',(2.17465028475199,-5.1,37.139035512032));
#2065=DIRECTION('',(0.,1.,0.));
#2066=DIRECTION('',(-1.,0.,0.));
#2067=AXIS2_PLACEMENT_3D('',#2064,#2065,#2066);
#2068=CYLINDRICAL_SURFACE('',#2067,2.5);
#2069=ORIENTED_EDGE('',*,*,#1668,.T.);
#2070=EDGE_LOOP('',(#2069));
#2071=FACE_BOUND('',#2070,.T.);
#2072=CARTESIAN_POINT('',(2.17465028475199,-5.1,37.139035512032));
#2073=DIRECTION('',(0.,1.,0.));
#2074=DIRECTION('',(-1.,0.,0.));
#2075=AXIS2_PLACEMENT_3D('',#2072,#2073,#2074);
#2076=CIRCLE('',#2075,2.5);
#2077=CARTESIAN_POINT('',(-0.325349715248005,-5.1,37.139035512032));
#2078=VERTEX_POINT('',#2077);
#2079=EDGE_CURVE('E530',#2078,#2078,#2076,.T.);
#2080=ORIENTED_EDGE('',*,*,#2079,.F.);
#2081=EDGE_LOOP('',(#2080));
#2082=FACE_BOUND('',#2081,.T.);
#2083=ADVANCED_FACE('F1160',(#2071,#2082),#2068,.F.);
#2084=CARTESIAN_POINT('',(0.583716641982,-5.1,30.637426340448));
#2085=DIRECTION('',(0.,1.,0.));
#2086=DIRECTION('',(-1.,0.,0.));
#2087=AXIS2_PLACEMENT_3D('',#2084,#2085,#2086);
#2088=CYLINDRICAL_SURFACE('',#2087,2.5);
#2089=ORIENTED_EDGE('',*,*,#1679,.T.);
#2090=EDGE_LOOP('',(#2089));
#2091=FACE_BOUND('',#2090,.T.);
#2092=CARTESIAN_POINT('',(0.583716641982,-5.1,30.637426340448));
#2093=DIRECTION('',(0.,1.,0.));
#2094=DIRECTION('',(-1.,0.,0.));
#2095=AXIS2_PLACEMENT_3D('',#2092,#2093,#2094);
#2096=CIRCLE('',#2095,2.5);
#2097=CARTESIAN_POINT('',(-1.916283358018,-5.1,30.637426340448));
#2098=VERTEX_POINT('',#2097);
#2099=EDGE_CURVE('E538',#2098,#2098,#2096,.T.);
#2100=ORIENTED_EDGE('',*,*,#2099,.F.);
#2101=EDGE_LOOP('',(#2100));
#2102=FACE_BOUND('',#2101,.T.);
#2103=ADVANCED_FACE('F1168',(#2091,#2102),#2088,.F.);
#2104=ORIENTED_EDGE('',*,*,#1499,.T.);
#2105=ORIENTED_EDGE('',*,*,#1701,.T.);
#2106=CARTESIAN_POINT('',(-9.,-5.1,17.72));
#2107=VERTEX_POINT('',#2106);
#2108=EDGE_CURVE('E813',#2107,#1691,#973,.T.);
#2109=ORIENTED_EDGE('',*,*,#2108,.F.);
#2110=CARTESIAN_POINT('',(-11.,-5.1,17.7199999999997));
#2111=DIRECTION('',(0.,-1.,0.));
#2112=DIRECTION('',(-1.,0.,0.));
#2113=AXIS2_PLACEMENT_3D('',#2110,#2111,#2112);
#2114=CIRCLE('',#2113,2.00000000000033);
#2115=EDGE_CURVE('E745',#2107,#1498,#2114,.T.);
#2116=ORIENTED_EDGE('',*,*,#2115,.T.);
#2117=EDGE_LOOP('',(#2104,#2105,#2109,#2116));
#2118=FACE_BOUND('',#2117,.T.);
#2119=ADVANCED_FACE('F1009',(#2118),#1204,.F.);
#2120=CARTESIAN_POINT('',(-11.,-1.0999999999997,63.22));
#2121=DIRECTION('',(0.,0.,-1.));
#2122=DIRECTION('',(0.,-1.,0.));
#2123=AXIS2_PLACEMENT_3D('',#2120,#2121,#2122);
#2124=CYLINDRICAL_SURFACE('',#2123,4.0000000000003);
#2125=DIRECTION('',(0.,0.,-1.));
#2126=VECTOR('',#2125,1.);
#2127=CARTESIAN_POINT('',(-11.,-5.1,63.22));
#2128=LINE('',#2127,#2126);
#2129=EDGE_CURVE('E549',#1560,#1498,#2128,.T.);
#2130=ORIENTED_EDGE('',*,*,#2129,.F.);
#2131=ORIENTED_EDGE('',*,*,#1561,.F.);
#2132=ORIENTED_EDGE('',*,*,#1535,.T.);
#2133=ORIENTED_EDGE('',*,*,#1508,.F.);
#2134=EDGE_LOOP('',(#2130,#2131,#2132,#2133));
#2135=FACE_BOUND('',#2134,.T.);
#2136=ADVANCED_FACE('F1051',(#2135),#2124,.T.);
#2137=CARTESIAN_POINT('',(-9.,-5.1,46.72));
#2138=VERTEX_POINT('',#2137);
#2139=EDGE_CURVE('E795',#2138,#1710,#1075,.T.);
#2140=ORIENTED_EDGE('',*,*,#2139,.T.);
#2141=ORIENTED_EDGE('',*,*,#1711,.T.);
#2142=ORIENTED_EDGE('',*,*,#1563,.F.);
#2143=CARTESIAN_POINT('',(-11.,-5.1,46.72));
#2144=DIRECTION('',(0.,-1.,0.));
#2145=DIRECTION('',(-1.,0.,0.));
#2146=AXIS2_PLACEMENT_3D('',#2143,#2144,#2145);
#2147=CIRCLE('',#2146,2.00000000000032);
#2148=EDGE_CURVE('E748',#1560,#2138,#2147,.T.);
#2149=ORIENTED_EDGE('',*,*,#2148,.T.);
#2150=EDGE_LOOP('',(#2140,#2141,#2142,#2149));
#2151=FACE_BOUND('',#2150,.T.);
#2152=ADVANCED_FACE('F1010',(#2151),#1254,.F.);
#2153=CARTESIAN_POINT('',(-9.,-5.1,58.22));
#2154=VERTEX_POINT('',#2153);
#2155=EDGE_CURVE('E791',#2154,#1718,#434,.T.);
#2156=ORIENTED_EDGE('',*,*,#2155,.T.);
#2157=ORIENTED_EDGE('',*,*,#1719,.T.);
#2158=ORIENTED_EDGE('',*,*,#2139,.F.);
#2159=DIRECTION('',(0.,0.,1.));
#2160=VECTOR('',#2159,1.);
#2161=CARTESIAN_POINT('',(-9.,-5.1,46.72));
#2162=LINE('',#2161,#2160);
#2163=EDGE_CURVE('E751',#2138,#2154,#2162,.T.);
#2164=ORIENTED_EDGE('',*,*,#2163,.T.);
#2165=EDGE_LOOP('',(#2156,#2157,#2158,#2164));
#2166=FACE_BOUND('',#2165,.T.);
#2167=ADVANCED_FACE('F1026',(#2166),#1071,.T.);
#2168=CARTESIAN_POINT('',(-4.,-5.1,63.22));
#2169=VERTEX_POINT('',#2168);
#2170=EDGE_CURVE('E787',#2169,#1727,#453,.T.);
#2171=ORIENTED_EDGE('',*,*,#2170,.T.);
#2172=ORIENTED_EDGE('',*,*,#1728,.T.);
#2173=ORIENTED_EDGE('',*,*,#2155,.F.);
#2174=CARTESIAN_POINT('',(-4.00000000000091,-5.1,58.2200000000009));
#2175=DIRECTION('',(0.,1.,0.));
#2176=DIRECTION('',(-1.,0.,0.));
#2177=AXIS2_PLACEMENT_3D('',#2174,#2175,#2176);
#2178=CIRCLE('',#2177,4.99999999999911);
#2179=EDGE_CURVE('E754',#2154,#2169,#2178,.T.);
#2180=ORIENTED_EDGE('',*,*,#2179,.T.);
#2181=EDGE_LOOP('',(#2171,#2172,#2173,#2180));
#2182=FACE_BOUND('',#2181,.T.);
#2183=ADVANCED_FACE('F1027',(#2182),#430,.T.);
#2184=CARTESIAN_POINT('',(0.48,-5.1,63.22));
#2185=VERTEX_POINT('',#2184);
#2186=EDGE_CURVE('E783',#2185,#1735,#485,.T.);
#2187=ORIENTED_EDGE('',*,*,#2186,.T.);
#2188=ORIENTED_EDGE('',*,*,#1736,.F.);
#2189=ORIENTED_EDGE('',*,*,#2170,.F.);
#2190=DIRECTION('',(1.,0.,0.));
#2191=VECTOR('',#2190,1.);
#2192=CARTESIAN_POINT('',(-4.,-5.1,63.22));
#2193=LINE('',#2192,#2191);
#2194=EDGE_CURVE('E756',#2169,#2185,#2193,.T.);
#2195=ORIENTED_EDGE('',*,*,#2194,.T.);
#2196=EDGE_LOOP('',(#2187,#2188,#2189,#2195));
#2197=FACE_BOUND('',#2196,.T.);
#2198=ADVANCED_FACE('F1059',(#2197),#472,.T.);
#2199=CARTESIAN_POINT('',(4.065259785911,-5.1,61.705098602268));
#2200=VERTEX_POINT('',#2199);
#2201=EDGE_CURVE('E779',#2200,#1744,#517,.T.);
#2202=ORIENTED_EDGE('',*,*,#2201,.T.);
#2203=ORIENTED_EDGE('',*,*,#1745,.T.);
#2204=ORIENTED_EDGE('',*,*,#2186,.F.);
#2205=CARTESIAN_POINT('',(0.480000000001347,-5.1,58.2200000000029));
#2206=DIRECTION('',(0.,1.,0.));
#2207=DIRECTION('',(-1.,0.,0.));
#2208=AXIS2_PLACEMENT_3D('',#2205,#2206,#2207);
#2209=CIRCLE('',#2208,4.99999999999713);
#2210=EDGE_CURVE('E759',#2185,#2200,#2209,.T.);
#2211=ORIENTED_EDGE('',*,*,#2210,.T.);
#2212=EDGE_LOOP('',(#2202,#2203,#2204,#2211));
#2213=FACE_BOUND('',#2212,.T.);
#2214=ADVANCED_FACE('F1064',(#2213),#503,.T.);
#2215=CARTESIAN_POINT('',(29.7364156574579,-5.1,35.296157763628));
#2216=VERTEX_POINT('',#2215);
#2217=EDGE_CURVE('E775',#2216,#1752,#549,.T.);
#2218=ORIENTED_EDGE('',*,*,#2217,.T.);
#2219=ORIENTED_EDGE('',*,*,#1753,.T.);
#2220=ORIENTED_EDGE('',*,*,#2201,.F.);
#2221=DIRECTION('',(0.697019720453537,0.,-0.717051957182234));
#2222=VECTOR('',#2221,1.);
#2223=CARTESIAN_POINT('',(4.065259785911,-5.1,61.705098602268));
#2224=LINE('',#2223,#2222);
#2225=EDGE_CURVE('E762',#2200,#2216,#2224,.T.);
#2226=ORIENTED_EDGE('',*,*,#2225,.T.);
#2227=EDGE_LOOP('',(#2218,#2219,#2220,#2226));
#2228=FACE_BOUND('',#2227,.T.);
#2229=ADVANCED_FACE('F1069',(#2228),#536,.T.);
#2230=CARTESIAN_POINT('',(32.,-5.1,29.72));
#2231=VERTEX_POINT('',#2230);
#2232=EDGE_CURVE('E771',#2231,#1761,#581,.T.);
#2233=ORIENTED_EDGE('',*,*,#2232,.T.);
#2234=ORIENTED_EDGE('',*,*,#1762,.T.);
#2235=ORIENTED_EDGE('',*,*,#2217,.F.);
#2236=CARTESIAN_POINT('',(24.0000000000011,-5.1,29.72));
#2237=DIRECTION('',(0.,1.,0.));
#2238=DIRECTION('',(-1.,0.,0.));
#2239=AXIS2_PLACEMENT_3D('',#2236,#2237,#2238);
#2240=CIRCLE('',#2239,7.99999999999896);
#2241=EDGE_CURVE('E765',#2216,#2231,#2240,.T.);
#2242=ORIENTED_EDGE('',*,*,#2241,.T.);
#2243=EDGE_LOOP('',(#2233,#2234,#2235,#2242));
#2244=FACE_BOUND('',#2243,.T.);
#2245=ADVANCED_FACE('F1074',(#2244),#567,.T.);
#2246=CARTESIAN_POINT('',(32.,-5.1,22.19));
#2247=VERTEX_POINT('',#2246);
#2248=EDGE_CURVE('E841',#2247,#1769,#613,.T.);
#2249=ORIENTED_EDGE('',*,*,#2248,.T.);
#2250=ORIENTED_EDGE('',*,*,#1770,.T.);
#2251=ORIENTED_EDGE('',*,*,#2232,.F.);
#2252=DIRECTION('',(0.,0.,-1.));
#2253=VECTOR('',#2252,1.);
#2254=CARTESIAN_POINT('',(32.,-5.1,29.72));
#2255=LINE('',#2254,#2253);
#2256=EDGE_CURVE('E722',#2231,#2247,#2255,.T.);
#2257=ORIENTED_EDGE('',*,*,#2256,.T.);
#2258=EDGE_LOOP('',(#2249,#2250,#2251,#2257));
#2259=FACE_BOUND('',#2258,.T.);
#2260=ADVANCED_FACE('F1040',(#2259),#600,.T.);
#2261=CARTESIAN_POINT('',(31.,-5.1,19.9539320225));
#2262=VERTEX_POINT('',#2261);
#2263=EDGE_CURVE('E837',#2262,#1778,#645,.T.);
#2264=ORIENTED_EDGE('',*,*,#2263,.T.);
#2265=ORIENTED_EDGE('',*,*,#1779,.T.);
#2266=ORIENTED_EDGE('',*,*,#2248,.F.);
#2267=CARTESIAN_POINT('',(29.0000000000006,-5.1,22.1899999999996));
#2268=DIRECTION('',(0.,1.,0.));
#2269=DIRECTION('',(-1.,0.,0.));
#2270=AXIS2_PLACEMENT_3D('',#2267,#2268,#2269);
#2271=CIRCLE('',#2270,2.99999999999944);
#2272=EDGE_CURVE('E725',#2247,#2262,#2271,.T.);
#2273=ORIENTED_EDGE('',*,*,#2272,.T.);
#2274=EDGE_LOOP('',(#2264,#2265,#2266,#2273));
#2275=FACE_BOUND('',#2274,.T.);
#2276=ADVANCED_FACE('F1277',(#2275),#631,.T.);
#2277=CARTESIAN_POINT('',(30.,-5.1,17.717864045));
#2278=VERTEX_POINT('',#2277);
#2279=EDGE_CURVE('E833',#2278,#1787,#678,.T.);
#2280=ORIENTED_EDGE('',*,*,#2279,.T.);
#2281=ORIENTED_EDGE('',*,*,#1788,.T.);
#2282=ORIENTED_EDGE('',*,*,#2263,.F.);
#2283=CARTESIAN_POINT('',(32.9999999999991,-5.1,17.7178640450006));
#2284=DIRECTION('',(0.,-1.,0.));
#2285=DIRECTION('',(1.,0.,0.));
#2286=AXIS2_PLACEMENT_3D('',#2283,#2284,#2285);
#2287=CIRCLE('',#2286,2.99999999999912);
#2288=EDGE_CURVE('E728',#2262,#2278,#2287,.T.);
#2289=ORIENTED_EDGE('',*,*,#2288,.T.);
#2290=EDGE_LOOP('',(#2280,#2281,#2282,#2289));
#2291=FACE_BOUND('',#2290,.T.);
#2292=ADVANCED_FACE('F1282',(#2291),#664,.F.);
#2293=CARTESIAN_POINT('',(30.,-5.1,-0.5));
#2294=VERTEX_POINT('',#2293);
#2295=EDGE_CURVE('E829',#2294,#1795,#710,.T.);
#2296=ORIENTED_EDGE('',*,*,#2295,.T.);
#2297=ORIENTED_EDGE('',*,*,#1796,.T.);
#2298=ORIENTED_EDGE('',*,*,#2279,.F.);
#2299=DIRECTION('',(0.,0.,-1.));
#2300=VECTOR('',#2299,1.);
#2301=CARTESIAN_POINT('',(30.,-5.1,17.717864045));
#2302=LINE('',#2301,#2300);
#2303=EDGE_CURVE('E731',#2278,#2294,#2302,.T.);
#2304=ORIENTED_EDGE('',*,*,#2303,.T.);
#2305=EDGE_LOOP('',(#2296,#2297,#2298,#2304));
#2306=FACE_BOUND('',#2305,.T.);
#2307=ADVANCED_FACE('F1284',(#2306),#697,.T.);
#2308=CARTESIAN_POINT('',(24.,-5.1,-6.5));
#2309=VERTEX_POINT('',#2308);
#2310=EDGE_CURVE('E825',#2309,#1804,#742,.T.);
#2311=ORIENTED_EDGE('',*,*,#2310,.T.);
#2312=ORIENTED_EDGE('',*,*,#1805,.T.);
#2313=ORIENTED_EDGE('',*,*,#2295,.F.);
#2314=CARTESIAN_POINT('',(24.,-5.1,-0.5));
#2315=DIRECTION('',(0.,1.,0.));
#2316=DIRECTION('',(-1.,0.,0.));
#2317=AXIS2_PLACEMENT_3D('',#2314,#2315,#2316);
#2318=CIRCLE('',#2317,6.);
#2319=EDGE_CURVE('E734',#2294,#2309,#2318,.T.);
#2320=ORIENTED_EDGE('',*,*,#2319,.T.);
#2321=EDGE_LOOP('',(#2311,#2312,#2313,#2320));
#2322=FACE_BOUND('',#2321,.T.);
#2323=ADVANCED_FACE('F1286',(#2322),#728,.T.);
#2324=CARTESIAN_POINT('',(-3.,-5.1,-6.5));
#2325=VERTEX_POINT('',#2324);
#2326=EDGE_CURVE('E821',#2325,#1812,#392,.T.);
#2327=ORIENTED_EDGE('',*,*,#2326,.T.);
#2328=ORIENTED_EDGE('',*,*,#1813,.T.);
#2329=ORIENTED_EDGE('',*,*,#2310,.F.);
#2330=DIRECTION('',(-1.,0.,0.));
#2331=VECTOR('',#2330,1.);
#2332=CARTESIAN_POINT('',(24.,-5.1,-6.5));
#2333=LINE('',#2332,#2331);
#2334=EDGE_CURVE('E737',#2309,#2325,#2333,.T.);
#2335=ORIENTED_EDGE('',*,*,#2334,.T.);
#2336=EDGE_LOOP('',(#2327,#2328,#2329,#2335));
#2337=FACE_BOUND('',#2336,.T.);
#2338=ADVANCED_FACE('F1289',(#2337),#761,.T.);
#2339=CARTESIAN_POINT('',(-9.,-5.1,-0.49999999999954));
#2340=VERTEX_POINT('',#2339);
#2341=EDGE_CURVE('E817',#2340,#1693,#411,.T.);
#2342=ORIENTED_EDGE('',*,*,#2341,.T.);
#2343=ORIENTED_EDGE('',*,*,#1820,.T.);
#2344=ORIENTED_EDGE('',*,*,#2326,.F.);
#2345=CARTESIAN_POINT('',(-2.99999999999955,-5.1,-0.49999999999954));
#2346=DIRECTION('',(0.,1.,0.));
#2347=DIRECTION('',(1.,0.,0.));
#2348=AXIS2_PLACEMENT_3D('',#2345,#2346,#2347);
#2349=CIRCLE('',#2348,6.00000000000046);
#2350=EDGE_CURVE('E740',#2325,#2340,#2349,.T.);
#2351=ORIENTED_EDGE('',*,*,#2350,.T.);
#2352=EDGE_LOOP('',(#2342,#2343,#2344,#2351));
#2353=FACE_BOUND('',#2352,.T.);
#2354=ADVANCED_FACE('F1292',(#2353),#388,.T.);
#2355=ORIENTED_EDGE('',*,*,#2108,.T.);
#2356=ORIENTED_EDGE('',*,*,#1694,.T.);
#2357=ORIENTED_EDGE('',*,*,#2341,.F.);
#2358=DIRECTION('',(0.,0.,1.));
#2359=VECTOR('',#2358,1.);
#2360=CARTESIAN_POINT('',(-9.,-5.1,-0.5));
#2361=LINE('',#2360,#2359);
#2362=EDGE_CURVE('E742',#2340,#2107,#2361,.T.);
#2363=ORIENTED_EDGE('',*,*,#2362,.T.);
#2364=EDGE_LOOP('',(#2355,#2356,#2357,#2363));
#2365=FACE_BOUND('',#2364,.T.);
#2366=ADVANCED_FACE('F921',(#2365),#960,.T.);
#2367=CARTESIAN_POINT('',(29.0000000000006,-5.1,22.1899999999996));
#2368=DIRECTION('',(0.,1.,0.));
#2369=DIRECTION('',(-1.,0.,0.));
#2370=AXIS2_PLACEMENT_3D('',#2367,#2368,#2369);
#2371=PLANE('',#2370);
#2372=ORIENTED_EDGE('',*,*,#2362,.F.);
#2373=ORIENTED_EDGE('',*,*,#2350,.F.);
#2374=ORIENTED_EDGE('',*,*,#2334,.F.);
#2375=ORIENTED_EDGE('',*,*,#2319,.F.);
#2376=ORIENTED_EDGE('',*,*,#2303,.F.);
#2377=ORIENTED_EDGE('',*,*,#2288,.F.);
#2378=ORIENTED_EDGE('',*,*,#2272,.F.);
#2379=ORIENTED_EDGE('',*,*,#2256,.F.);
#2380=ORIENTED_EDGE('',*,*,#2241,.F.);
#2381=ORIENTED_EDGE('',*,*,#2225,.F.);
#2382=ORIENTED_EDGE('',*,*,#2210,.F.);
#2383=ORIENTED_EDGE('',*,*,#2194,.F.);
#2384=ORIENTED_EDGE('',*,*,#2179,.F.);
#2385=ORIENTED_EDGE('',*,*,#2163,.F.);
#2386=ORIENTED_EDGE('',*,*,#2148,.F.);
#2387=ORIENTED_EDGE('',*,*,#2129,.T.);
#2388=ORIENTED_EDGE('',*,*,#2115,.F.);
#2389=EDGE_LOOP('',(#2372,#2373,#2374,#2375,#2376,#2377,#2378,#2379,#2380,#2381,#2382,#2383,
#2384,#2385,#2386,#2387,#2388));
#2390=FACE_BOUND('',#2389,.T.);
#2391=ORIENTED_EDGE('',*,*,#2099,.T.);
#2392=EDGE_LOOP('',(#2391));
#2393=FACE_BOUND('',#2392,.T.);
#2394=ORIENTED_EDGE('',*,*,#2079,.T.);
#2395=EDGE_LOOP('',(#2394));
#2396=FACE_BOUND('',#2395,.T.);
#2397=ORIENTED_EDGE('',*,*,#2059,.T.);
#2398=EDGE_LOOP('',(#2397));
#2399=FACE_BOUND('',#2398,.T.);
#2400=ORIENTED_EDGE('',*,*,#2038,.T.);
#2401=ORIENTED_EDGE('',*,*,#2015,.T.);
#2402=ORIENTED_EDGE('',*,*,#1991,.T.);
#2403=ORIENTED_EDGE('',*,*,#1966,.T.);
#2404=EDGE_LOOP('',(#2400,#2401,#2402,#2403));
#2405=FACE_BOUND('',#2404,.T.);
#2406=ORIENTED_EDGE('',*,*,#1940,.T.);
#2407=ORIENTED_EDGE('',*,*,#1917,.T.);
#2408=ORIENTED_EDGE('',*,*,#1893,.T.);
#2409=ORIENTED_EDGE('',*,*,#1868,.T.);
#2410=EDGE_LOOP('',(#2406,#2407,#2408,#2409));
#2411=FACE_BOUND('',#2410,.T.);
#2412=ORIENTED_EDGE('',*,*,#1843,.T.);
#2413=EDGE_LOOP('',(#2412));
#2414=FACE_BOUND('',#2413,.T.);
#2415=ORIENTED_EDGE('',*,*,#90,.F.);
#2416=EDGE_LOOP('',(#2415));
#2417=FACE_BOUND('',#2416,.T.);
#2418=ADVANCED_FACE('F917',(#2390,#2393,#2396,#2399,#2405,#2411,#2414,#2417),#2371,.F.);
#2419=CARTESIAN_POINT('',(22.5,7.1,22.97));
#2420=DIRECTION('',(0.,-1.,0.));
#2421=DIRECTION('',(-1.,0.,0.));
#2422=AXIS2_PLACEMENT_3D('',#2419,#2420,#2421);
#2423=PLANE('',#2422);
#2424=ORIENTED_EDGE('',*,*,#59,.F.);
#2425=EDGE_LOOP('',(#2424));
#2426=FACE_BOUND('',#2425,.T.);
#2427=ORIENTED_EDGE('',*,*,#107,.T.);
#2428=EDGE_LOOP('',(#2427));
#2429=FACE_BOUND('',#2428,.T.);
#2430=ADVANCED_FACE('F920',(#2426,#2429),#2423,.F.);
#2431=CARTESIAN_POINT('',(22.5,-7.1,28.72));
#2432=DIRECTION('',(0.,-1.,0.));
#2433=DIRECTION('',(1.,0.,0.));
#2434=AXIS2_PLACEMENT_3D('',#2431,#2432,#2433);
#2435=PLANE('',#2434);
#2436=CARTESIAN_POINT('',(22.5,-7.1,28.72));
#2437=DIRECTION('',(0.,-1.,0.));
#2438=DIRECTION('',(1.,0.,0.));
#2439=AXIS2_PLACEMENT_3D('',#2436,#2437,#2438);
#2440=CIRCLE('',#2439,5.75);
#2441=CARTESIAN_POINT('',(28.25,-7.1,28.72));
#2442=VERTEX_POINT('',#2441);
#2443=EDGE_CURVE('E23',#2442,#2442,#2440,.T.);
#2444=ORIENTED_EDGE('',*,*,#2443,.T.);
#2445=EDGE_LOOP('',(#2444));
#2446=FACE_BOUND('',#2445,.T.);
#2447=ORIENTED_EDGE('',*,*,#70,.T.);
#2448=EDGE_LOOP('',(#2447));
#2449=FACE_BOUND('',#2448,.T.);
#2450=ADVANCED_FACE('F969',(#2446,#2449),#2435,.T.);
#2451=CARTESIAN_POINT('',(22.5,-7.1,28.72));
#2452=DIRECTION('',(0.,1.,0.));
#2453=DIRECTION('',(-1.,0.,0.));
#2454=AXIS2_PLACEMENT_3D('',#2451,#2452,#2453);
#2455=CONICAL_SURFACE('',#2454,5.75,0.785398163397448);
#2456=ORIENTED_EDGE('',*,*,#31,.F.);
#2457=EDGE_LOOP('',(#2456));
#2458=FACE_BOUND('',#2457,.T.);
#2459=ORIENTED_EDGE('',*,*,#2443,.F.);
#2460=EDGE_LOOP('',(#2459));
#2461=FACE_BOUND('',#2460,.T.);
#2462=ADVANCED_FACE('F16',(#2458,#2461),#2455,.T.);
#2463=CLOSED_SHELL('',(#46,#74,#94,#122,#142,#159,#179,#199,#239,#272,#303,#327,#355,#383,#425,
#467,#498,#531,#562,#595,#626,#659,#692,#723,#756,#778,#806,#846,#879,#910,#934,#955,#986,#1066,
#1090,#1179,#1199,#1216,#1249,#1266,#1299,#1330,#1363,#1383,#1403,#1491,#1523,#1547,#1572,#1827,
#1847,#1878,#1903,#1927,#1945,#1976,#2001,#2025,#2043,#2063,#2083,#2103,#2119,#2136,#2152,#2167,
#2183,#2198,#2214,#2229,#2245,#2260,#2276,#2292,#2307,#2323,#2338,#2354,#2366,#2418,#2430,#2450,#2462));
#2464=MANIFOLD_SOLID_BREP('B1',#2463);
#2465=ADVANCED_BREP_SHAPE_REPRESENTATION('',(#18,#2464),#14);
#2466=SHAPE_DEFINITION_REPRESENTATION(#9,#2465);
ENDSEC;
END-ISO-10303-21;
